# Generated deterministically by seda-macro-lef-normalizer-v1; recipe orfs-asap7-fakeram-m4-v1.
VERSION 5.8 ;
BUSBITCHARS "[]" ;
DIVIDERCHAR "/" ;

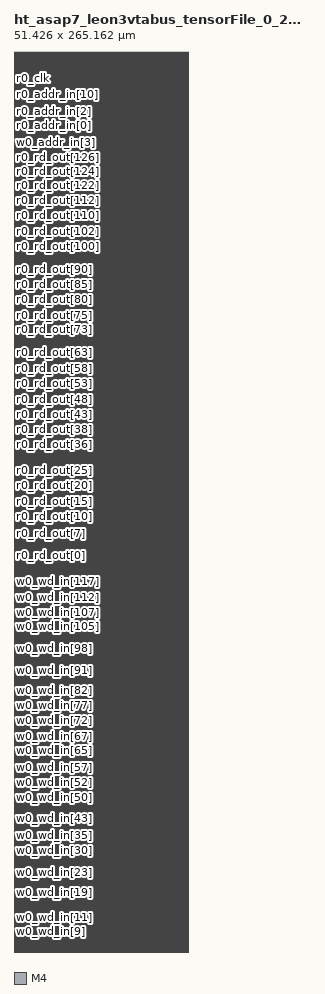
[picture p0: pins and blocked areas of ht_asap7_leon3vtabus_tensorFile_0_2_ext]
MACRO ht_asap7_leon3vtabus_tensorFile_0_2_ext
  FOREIGN ht_asap7_leon3vtabus_tensorFile_0_2_ext 0 0 ;
  CLASS BLOCK ;
  ORIGIN 0 0 ;
  SIZE 51.426 BY 265.162 ;
  SYMMETRY X Y R90 ;
  PIN w0_wd_in[0]
    DIRECTION INPUT ;
    USE SIGNAL ;
    SHAPE ABUTMENT ;
    PORT
      LAYER M4 ;
      RECT 0 0.048 0.024 0.072 ;
    END
  END w0_wd_in[0]
  PIN w0_wd_in[1]
    DIRECTION INPUT ;
    USE SIGNAL ;
    SHAPE ABUTMENT ;
    PORT
      LAYER M4 ;
      RECT 0 0.96 0.024 0.984 ;
    END
  END w0_wd_in[1]
  PIN w0_wd_in[2]
    DIRECTION INPUT ;
    USE SIGNAL ;
    SHAPE ABUTMENT ;
    PORT
      LAYER M4 ;
      RECT 0 1.872 0.024 1.896 ;
    END
  END w0_wd_in[2]
  PIN w0_wd_in[3]
    DIRECTION INPUT ;
    USE SIGNAL ;
    SHAPE ABUTMENT ;
    PORT
      LAYER M4 ;
      RECT 0 2.784 0.024 2.808 ;
    END
  END w0_wd_in[3]
  PIN w0_wd_in[4]
    DIRECTION INPUT ;
    USE SIGNAL ;
    SHAPE ABUTMENT ;
    PORT
      LAYER M4 ;
      RECT 0 3.696 0.024 3.72 ;
    END
  END w0_wd_in[4]
  PIN w0_wd_in[5]
    DIRECTION INPUT ;
    USE SIGNAL ;
    SHAPE ABUTMENT ;
    PORT
      LAYER M4 ;
      RECT 0 4.608 0.024 4.632 ;
    END
  END w0_wd_in[5]
  PIN w0_wd_in[6]
    DIRECTION INPUT ;
    USE SIGNAL ;
    SHAPE ABUTMENT ;
    PORT
      LAYER M4 ;
      RECT 0 5.52 0.024 5.544 ;
    END
  END w0_wd_in[6]
  PIN w0_wd_in[7]
    DIRECTION INPUT ;
    USE SIGNAL ;
    SHAPE ABUTMENT ;
    PORT
      LAYER M4 ;
      RECT 0 6.432 0.024 6.456 ;
    END
  END w0_wd_in[7]
  PIN w0_wd_in[8]
    DIRECTION INPUT ;
    USE SIGNAL ;
    SHAPE ABUTMENT ;
    PORT
      LAYER M4 ;
      RECT 0 7.344 0.024 7.368 ;
    END
  END w0_wd_in[8]
  PIN w0_wd_in[9]
    DIRECTION INPUT ;
    USE SIGNAL ;
    SHAPE ABUTMENT ;
    PORT
      LAYER M4 ;
      RECT 0 8.256 0.024 8.28 ;
    END
  END w0_wd_in[9]
  PIN w0_wd_in[10]
    DIRECTION INPUT ;
    USE SIGNAL ;
    SHAPE ABUTMENT ;
    PORT
      LAYER M4 ;
      RECT 0 9.168 0.024 9.192 ;
    END
  END w0_wd_in[10]
  PIN w0_wd_in[11]
    DIRECTION INPUT ;
    USE SIGNAL ;
    SHAPE ABUTMENT ;
    PORT
      LAYER M4 ;
      RECT 0 10.08 0.024 10.104 ;
    END
  END w0_wd_in[11]
  PIN w0_wd_in[12]
    DIRECTION INPUT ;
    USE SIGNAL ;
    SHAPE ABUTMENT ;
    PORT
      LAYER M4 ;
      RECT 0 10.992 0.024 11.016 ;
    END
  END w0_wd_in[12]
  PIN w0_wd_in[13]
    DIRECTION INPUT ;
    USE SIGNAL ;
    SHAPE ABUTMENT ;
    PORT
      LAYER M4 ;
      RECT 0 11.904 0.024 11.928 ;
    END
  END w0_wd_in[13]
  PIN w0_wd_in[14]
    DIRECTION INPUT ;
    USE SIGNAL ;
    SHAPE ABUTMENT ;
    PORT
      LAYER M4 ;
      RECT 0 12.816 0.024 12.84 ;
    END
  END w0_wd_in[14]
  PIN w0_wd_in[15]
    DIRECTION INPUT ;
    USE SIGNAL ;
    SHAPE ABUTMENT ;
    PORT
      LAYER M4 ;
      RECT 0 13.728 0.024 13.752 ;
    END
  END w0_wd_in[15]
  PIN w0_wd_in[16]
    DIRECTION INPUT ;
    USE SIGNAL ;
    SHAPE ABUTMENT ;
    PORT
      LAYER M4 ;
      RECT 0 14.64 0.024 14.664 ;
    END
  END w0_wd_in[16]
  PIN w0_wd_in[17]
    DIRECTION INPUT ;
    USE SIGNAL ;
    SHAPE ABUTMENT ;
    PORT
      LAYER M4 ;
      RECT 0 15.552 0.024 15.576 ;
    END
  END w0_wd_in[17]
  PIN w0_wd_in[18]
    DIRECTION INPUT ;
    USE SIGNAL ;
    SHAPE ABUTMENT ;
    PORT
      LAYER M4 ;
      RECT 0 16.464 0.024 16.488 ;
    END
  END w0_wd_in[18]
  PIN w0_wd_in[19]
    DIRECTION INPUT ;
    USE SIGNAL ;
    SHAPE ABUTMENT ;
    PORT
      LAYER M4 ;
      RECT 0 17.376 0.024 17.4 ;
    END
  END w0_wd_in[19]
  PIN w0_wd_in[20]
    DIRECTION INPUT ;
    USE SIGNAL ;
    SHAPE ABUTMENT ;
    PORT
      LAYER M4 ;
      RECT 0 18.288 0.024 18.312 ;
    END
  END w0_wd_in[20]
  PIN w0_wd_in[21]
    DIRECTION INPUT ;
    USE SIGNAL ;
    SHAPE ABUTMENT ;
    PORT
      LAYER M4 ;
      RECT 0 19.2 0.024 19.224 ;
    END
  END w0_wd_in[21]
  PIN w0_wd_in[22]
    DIRECTION INPUT ;
    USE SIGNAL ;
    SHAPE ABUTMENT ;
    PORT
      LAYER M4 ;
      RECT 0 20.112 0.024 20.136 ;
    END
  END w0_wd_in[22]
  PIN w0_wd_in[23]
    DIRECTION INPUT ;
    USE SIGNAL ;
    SHAPE ABUTMENT ;
    PORT
      LAYER M4 ;
      RECT 0 21.024 0.024 21.048 ;
    END
  END w0_wd_in[23]
  PIN w0_wd_in[24]
    DIRECTION INPUT ;
    USE SIGNAL ;
    SHAPE ABUTMENT ;
    PORT
      LAYER M4 ;
      RECT 0 21.936 0.024 21.96 ;
    END
  END w0_wd_in[24]
  PIN w0_wd_in[25]
    DIRECTION INPUT ;
    USE SIGNAL ;
    SHAPE ABUTMENT ;
    PORT
      LAYER M4 ;
      RECT 0 22.848 0.024 22.872 ;
    END
  END w0_wd_in[25]
  PIN w0_wd_in[26]
    DIRECTION INPUT ;
    USE SIGNAL ;
    SHAPE ABUTMENT ;
    PORT
      LAYER M4 ;
      RECT 0 23.76 0.024 23.784 ;
    END
  END w0_wd_in[26]
  PIN w0_wd_in[27]
    DIRECTION INPUT ;
    USE SIGNAL ;
    SHAPE ABUTMENT ;
    PORT
      LAYER M4 ;
      RECT 0 24.672 0.024 24.696 ;
    END
  END w0_wd_in[27]
  PIN w0_wd_in[28]
    DIRECTION INPUT ;
    USE SIGNAL ;
    SHAPE ABUTMENT ;
    PORT
      LAYER M4 ;
      RECT 0 25.584 0.024 25.608 ;
    END
  END w0_wd_in[28]
  PIN w0_wd_in[29]
    DIRECTION INPUT ;
    USE SIGNAL ;
    SHAPE ABUTMENT ;
    PORT
      LAYER M4 ;
      RECT 0 26.496 0.024 26.52 ;
    END
  END w0_wd_in[29]
  PIN w0_wd_in[30]
    DIRECTION INPUT ;
    USE SIGNAL ;
    SHAPE ABUTMENT ;
    PORT
      LAYER M4 ;
      RECT 0 27.408 0.024 27.432 ;
    END
  END w0_wd_in[30]
  PIN w0_wd_in[31]
    DIRECTION INPUT ;
    USE SIGNAL ;
    SHAPE ABUTMENT ;
    PORT
      LAYER M4 ;
      RECT 0 28.32 0.024 28.344 ;
    END
  END w0_wd_in[31]
  PIN w0_wd_in[32]
    DIRECTION INPUT ;
    USE SIGNAL ;
    SHAPE ABUTMENT ;
    PORT
      LAYER M4 ;
      RECT 0 29.232 0.024 29.256 ;
    END
  END w0_wd_in[32]
  PIN w0_wd_in[33]
    DIRECTION INPUT ;
    USE SIGNAL ;
    SHAPE ABUTMENT ;
    PORT
      LAYER M4 ;
      RECT 0 30.144 0.024 30.168 ;
    END
  END w0_wd_in[33]
  PIN w0_wd_in[34]
    DIRECTION INPUT ;
    USE SIGNAL ;
    SHAPE ABUTMENT ;
    PORT
      LAYER M4 ;
      RECT 0 31.056 0.024 31.08 ;
    END
  END w0_wd_in[34]
  PIN w0_wd_in[35]
    DIRECTION INPUT ;
    USE SIGNAL ;
    SHAPE ABUTMENT ;
    PORT
      LAYER M4 ;
      RECT 0 31.968 0.024 31.992 ;
    END
  END w0_wd_in[35]
  PIN w0_wd_in[36]
    DIRECTION INPUT ;
    USE SIGNAL ;
    SHAPE ABUTMENT ;
    PORT
      LAYER M4 ;
      RECT 0 32.88 0.024 32.904 ;
    END
  END w0_wd_in[36]
  PIN w0_wd_in[37]
    DIRECTION INPUT ;
    USE SIGNAL ;
    SHAPE ABUTMENT ;
    PORT
      LAYER M4 ;
      RECT 0 33.792 0.024 33.816 ;
    END
  END w0_wd_in[37]
  PIN w0_wd_in[38]
    DIRECTION INPUT ;
    USE SIGNAL ;
    SHAPE ABUTMENT ;
    PORT
      LAYER M4 ;
      RECT 0 34.704 0.024 34.728 ;
    END
  END w0_wd_in[38]
  PIN w0_wd_in[39]
    DIRECTION INPUT ;
    USE SIGNAL ;
    SHAPE ABUTMENT ;
    PORT
      LAYER M4 ;
      RECT 0 35.616 0.024 35.64 ;
    END
  END w0_wd_in[39]
  PIN w0_wd_in[40]
    DIRECTION INPUT ;
    USE SIGNAL ;
    SHAPE ABUTMENT ;
    PORT
      LAYER M4 ;
      RECT 0 36.528 0.024 36.552 ;
    END
  END w0_wd_in[40]
  PIN w0_wd_in[41]
    DIRECTION INPUT ;
    USE SIGNAL ;
    SHAPE ABUTMENT ;
    PORT
      LAYER M4 ;
      RECT 0 37.44 0.024 37.464 ;
    END
  END w0_wd_in[41]
  PIN w0_wd_in[42]
    DIRECTION INPUT ;
    USE SIGNAL ;
    SHAPE ABUTMENT ;
    PORT
      LAYER M4 ;
      RECT 0 38.352 0.024 38.376 ;
    END
  END w0_wd_in[42]
  PIN w0_wd_in[43]
    DIRECTION INPUT ;
    USE SIGNAL ;
    SHAPE ABUTMENT ;
    PORT
      LAYER M4 ;
      RECT 0 39.264 0.024 39.288 ;
    END
  END w0_wd_in[43]
  PIN w0_wd_in[44]
    DIRECTION INPUT ;
    USE SIGNAL ;
    SHAPE ABUTMENT ;
    PORT
      LAYER M4 ;
      RECT 0 40.176 0.024 40.2 ;
    END
  END w0_wd_in[44]
  PIN w0_wd_in[45]
    DIRECTION INPUT ;
    USE SIGNAL ;
    SHAPE ABUTMENT ;
    PORT
      LAYER M4 ;
      RECT 0 41.088 0.024 41.112 ;
    END
  END w0_wd_in[45]
  PIN w0_wd_in[46]
    DIRECTION INPUT ;
    USE SIGNAL ;
    SHAPE ABUTMENT ;
    PORT
      LAYER M4 ;
      RECT 0 42 0.024 42.024 ;
    END
  END w0_wd_in[46]
  PIN w0_wd_in[47]
    DIRECTION INPUT ;
    USE SIGNAL ;
    SHAPE ABUTMENT ;
    PORT
      LAYER M4 ;
      RECT 0 42.912 0.024 42.936 ;
    END
  END w0_wd_in[47]
  PIN w0_wd_in[48]
    DIRECTION INPUT ;
    USE SIGNAL ;
    SHAPE ABUTMENT ;
    PORT
      LAYER M4 ;
      RECT 0 43.824 0.024 43.848 ;
    END
  END w0_wd_in[48]
  PIN w0_wd_in[49]
    DIRECTION INPUT ;
    USE SIGNAL ;
    SHAPE ABUTMENT ;
    PORT
      LAYER M4 ;
      RECT 0 44.736 0.024 44.76 ;
    END
  END w0_wd_in[49]
  PIN w0_wd_in[50]
    DIRECTION INPUT ;
    USE SIGNAL ;
    SHAPE ABUTMENT ;
    PORT
      LAYER M4 ;
      RECT 0 45.648 0.024 45.672 ;
    END
  END w0_wd_in[50]
  PIN w0_wd_in[51]
    DIRECTION INPUT ;
    USE SIGNAL ;
    SHAPE ABUTMENT ;
    PORT
      LAYER M4 ;
      RECT 0 46.56 0.024 46.584 ;
    END
  END w0_wd_in[51]
  PIN w0_wd_in[52]
    DIRECTION INPUT ;
    USE SIGNAL ;
    SHAPE ABUTMENT ;
    PORT
      LAYER M4 ;
      RECT 0 47.472 0.024 47.496 ;
    END
  END w0_wd_in[52]
  PIN w0_wd_in[53]
    DIRECTION INPUT ;
    USE SIGNAL ;
    SHAPE ABUTMENT ;
    PORT
      LAYER M4 ;
      RECT 0 48.384 0.024 48.408 ;
    END
  END w0_wd_in[53]
  PIN w0_wd_in[54]
    DIRECTION INPUT ;
    USE SIGNAL ;
    SHAPE ABUTMENT ;
    PORT
      LAYER M4 ;
      RECT 0 49.296 0.024 49.32 ;
    END
  END w0_wd_in[54]
  PIN w0_wd_in[55]
    DIRECTION INPUT ;
    USE SIGNAL ;
    SHAPE ABUTMENT ;
    PORT
      LAYER M4 ;
      RECT 0 50.208 0.024 50.232 ;
    END
  END w0_wd_in[55]
  PIN w0_wd_in[56]
    DIRECTION INPUT ;
    USE SIGNAL ;
    SHAPE ABUTMENT ;
    PORT
      LAYER M4 ;
      RECT 0 51.12 0.024 51.144 ;
    END
  END w0_wd_in[56]
  PIN w0_wd_in[57]
    DIRECTION INPUT ;
    USE SIGNAL ;
    SHAPE ABUTMENT ;
    PORT
      LAYER M4 ;
      RECT 0 52.032 0.024 52.056 ;
    END
  END w0_wd_in[57]
  PIN w0_wd_in[58]
    DIRECTION INPUT ;
    USE SIGNAL ;
    SHAPE ABUTMENT ;
    PORT
      LAYER M4 ;
      RECT 0 52.944 0.024 52.968 ;
    END
  END w0_wd_in[58]
  PIN w0_wd_in[59]
    DIRECTION INPUT ;
    USE SIGNAL ;
    SHAPE ABUTMENT ;
    PORT
      LAYER M4 ;
      RECT 0 53.856 0.024 53.88 ;
    END
  END w0_wd_in[59]
  PIN w0_wd_in[60]
    DIRECTION INPUT ;
    USE SIGNAL ;
    SHAPE ABUTMENT ;
    PORT
      LAYER M4 ;
      RECT 0 54.768 0.024 54.792 ;
    END
  END w0_wd_in[60]
  PIN w0_wd_in[61]
    DIRECTION INPUT ;
    USE SIGNAL ;
    SHAPE ABUTMENT ;
    PORT
      LAYER M4 ;
      RECT 0 55.68 0.024 55.704 ;
    END
  END w0_wd_in[61]
  PIN w0_wd_in[62]
    DIRECTION INPUT ;
    USE SIGNAL ;
    SHAPE ABUTMENT ;
    PORT
      LAYER M4 ;
      RECT 0 56.592 0.024 56.616 ;
    END
  END w0_wd_in[62]
  PIN w0_wd_in[63]
    DIRECTION INPUT ;
    USE SIGNAL ;
    SHAPE ABUTMENT ;
    PORT
      LAYER M4 ;
      RECT 0 57.504 0.024 57.528 ;
    END
  END w0_wd_in[63]
  PIN w0_wd_in[64]
    DIRECTION INPUT ;
    USE SIGNAL ;
    SHAPE ABUTMENT ;
    PORT
      LAYER M4 ;
      RECT 0 58.416 0.024 58.44 ;
    END
  END w0_wd_in[64]
  PIN w0_wd_in[65]
    DIRECTION INPUT ;
    USE SIGNAL ;
    SHAPE ABUTMENT ;
    PORT
      LAYER M4 ;
      RECT 0 59.328 0.024 59.352 ;
    END
  END w0_wd_in[65]
  PIN w0_wd_in[66]
    DIRECTION INPUT ;
    USE SIGNAL ;
    SHAPE ABUTMENT ;
    PORT
      LAYER M4 ;
      RECT 0 60.24 0.024 60.264 ;
    END
  END w0_wd_in[66]
  PIN w0_wd_in[67]
    DIRECTION INPUT ;
    USE SIGNAL ;
    SHAPE ABUTMENT ;
    PORT
      LAYER M4 ;
      RECT 0 61.152 0.024 61.176 ;
    END
  END w0_wd_in[67]
  PIN w0_wd_in[68]
    DIRECTION INPUT ;
    USE SIGNAL ;
    SHAPE ABUTMENT ;
    PORT
      LAYER M4 ;
      RECT 0 62.064 0.024 62.088 ;
    END
  END w0_wd_in[68]
  PIN w0_wd_in[69]
    DIRECTION INPUT ;
    USE SIGNAL ;
    SHAPE ABUTMENT ;
    PORT
      LAYER M4 ;
      RECT 0 62.976 0.024 63 ;
    END
  END w0_wd_in[69]
  PIN w0_wd_in[70]
    DIRECTION INPUT ;
    USE SIGNAL ;
    SHAPE ABUTMENT ;
    PORT
      LAYER M4 ;
      RECT 0 63.888 0.024 63.912 ;
    END
  END w0_wd_in[70]
  PIN w0_wd_in[71]
    DIRECTION INPUT ;
    USE SIGNAL ;
    SHAPE ABUTMENT ;
    PORT
      LAYER M4 ;
      RECT 0 64.8 0.024 64.824 ;
    END
  END w0_wd_in[71]
  PIN w0_wd_in[72]
    DIRECTION INPUT ;
    USE SIGNAL ;
    SHAPE ABUTMENT ;
    PORT
      LAYER M4 ;
      RECT 0 65.712 0.024 65.736 ;
    END
  END w0_wd_in[72]
  PIN w0_wd_in[73]
    DIRECTION INPUT ;
    USE SIGNAL ;
    SHAPE ABUTMENT ;
    PORT
      LAYER M4 ;
      RECT 0 66.624 0.024 66.648 ;
    END
  END w0_wd_in[73]
  PIN w0_wd_in[74]
    DIRECTION INPUT ;
    USE SIGNAL ;
    SHAPE ABUTMENT ;
    PORT
      LAYER M4 ;
      RECT 0 67.536 0.024 67.56 ;
    END
  END w0_wd_in[74]
  PIN w0_wd_in[75]
    DIRECTION INPUT ;
    USE SIGNAL ;
    SHAPE ABUTMENT ;
    PORT
      LAYER M4 ;
      RECT 0 68.448 0.024 68.472 ;
    END
  END w0_wd_in[75]
  PIN w0_wd_in[76]
    DIRECTION INPUT ;
    USE SIGNAL ;
    SHAPE ABUTMENT ;
    PORT
      LAYER M4 ;
      RECT 0 69.36 0.024 69.384 ;
    END
  END w0_wd_in[76]
  PIN w0_wd_in[77]
    DIRECTION INPUT ;
    USE SIGNAL ;
    SHAPE ABUTMENT ;
    PORT
      LAYER M4 ;
      RECT 0 70.272 0.024 70.296 ;
    END
  END w0_wd_in[77]
  PIN w0_wd_in[78]
    DIRECTION INPUT ;
    USE SIGNAL ;
    SHAPE ABUTMENT ;
    PORT
      LAYER M4 ;
      RECT 0 71.184 0.024 71.208 ;
    END
  END w0_wd_in[78]
  PIN w0_wd_in[79]
    DIRECTION INPUT ;
    USE SIGNAL ;
    SHAPE ABUTMENT ;
    PORT
      LAYER M4 ;
      RECT 0 72.096 0.024 72.12 ;
    END
  END w0_wd_in[79]
  PIN w0_wd_in[80]
    DIRECTION INPUT ;
    USE SIGNAL ;
    SHAPE ABUTMENT ;
    PORT
      LAYER M4 ;
      RECT 0 73.008 0.024 73.032 ;
    END
  END w0_wd_in[80]
  PIN w0_wd_in[81]
    DIRECTION INPUT ;
    USE SIGNAL ;
    SHAPE ABUTMENT ;
    PORT
      LAYER M4 ;
      RECT 0 73.92 0.024 73.944 ;
    END
  END w0_wd_in[81]
  PIN w0_wd_in[82]
    DIRECTION INPUT ;
    USE SIGNAL ;
    SHAPE ABUTMENT ;
    PORT
      LAYER M4 ;
      RECT 0 74.832 0.024 74.856 ;
    END
  END w0_wd_in[82]
  PIN w0_wd_in[83]
    DIRECTION INPUT ;
    USE SIGNAL ;
    SHAPE ABUTMENT ;
    PORT
      LAYER M4 ;
      RECT 0 75.744 0.024 75.768 ;
    END
  END w0_wd_in[83]
  PIN w0_wd_in[84]
    DIRECTION INPUT ;
    USE SIGNAL ;
    SHAPE ABUTMENT ;
    PORT
      LAYER M4 ;
      RECT 0 76.656 0.024 76.68 ;
    END
  END w0_wd_in[84]
  PIN w0_wd_in[85]
    DIRECTION INPUT ;
    USE SIGNAL ;
    SHAPE ABUTMENT ;
    PORT
      LAYER M4 ;
      RECT 0 77.568 0.024 77.592 ;
    END
  END w0_wd_in[85]
  PIN w0_wd_in[86]
    DIRECTION INPUT ;
    USE SIGNAL ;
    SHAPE ABUTMENT ;
    PORT
      LAYER M4 ;
      RECT 0 78.48 0.024 78.504 ;
    END
  END w0_wd_in[86]
  PIN w0_wd_in[87]
    DIRECTION INPUT ;
    USE SIGNAL ;
    SHAPE ABUTMENT ;
    PORT
      LAYER M4 ;
      RECT 0 79.392 0.024 79.416 ;
    END
  END w0_wd_in[87]
  PIN w0_wd_in[88]
    DIRECTION INPUT ;
    USE SIGNAL ;
    SHAPE ABUTMENT ;
    PORT
      LAYER M4 ;
      RECT 0 80.304 0.024 80.328 ;
    END
  END w0_wd_in[88]
  PIN w0_wd_in[89]
    DIRECTION INPUT ;
    USE SIGNAL ;
    SHAPE ABUTMENT ;
    PORT
      LAYER M4 ;
      RECT 0 81.216 0.024 81.24 ;
    END
  END w0_wd_in[89]
  PIN w0_wd_in[90]
    DIRECTION INPUT ;
    USE SIGNAL ;
    SHAPE ABUTMENT ;
    PORT
      LAYER M4 ;
      RECT 0 82.128 0.024 82.152 ;
    END
  END w0_wd_in[90]
  PIN w0_wd_in[91]
    DIRECTION INPUT ;
    USE SIGNAL ;
    SHAPE ABUTMENT ;
    PORT
      LAYER M4 ;
      RECT 0 83.04 0.024 83.064 ;
    END
  END w0_wd_in[91]
  PIN w0_wd_in[92]
    DIRECTION INPUT ;
    USE SIGNAL ;
    SHAPE ABUTMENT ;
    PORT
      LAYER M4 ;
      RECT 0 83.952 0.024 83.976 ;
    END
  END w0_wd_in[92]
  PIN w0_wd_in[93]
    DIRECTION INPUT ;
    USE SIGNAL ;
    SHAPE ABUTMENT ;
    PORT
      LAYER M4 ;
      RECT 0 84.864 0.024 84.888 ;
    END
  END w0_wd_in[93]
  PIN w0_wd_in[94]
    DIRECTION INPUT ;
    USE SIGNAL ;
    SHAPE ABUTMENT ;
    PORT
      LAYER M4 ;
      RECT 0 85.776 0.024 85.8 ;
    END
  END w0_wd_in[94]
  PIN w0_wd_in[95]
    DIRECTION INPUT ;
    USE SIGNAL ;
    SHAPE ABUTMENT ;
    PORT
      LAYER M4 ;
      RECT 0 86.688 0.024 86.712 ;
    END
  END w0_wd_in[95]
  PIN w0_wd_in[96]
    DIRECTION INPUT ;
    USE SIGNAL ;
    SHAPE ABUTMENT ;
    PORT
      LAYER M4 ;
      RECT 0 87.6 0.024 87.624 ;
    END
  END w0_wd_in[96]
  PIN w0_wd_in[97]
    DIRECTION INPUT ;
    USE SIGNAL ;
    SHAPE ABUTMENT ;
    PORT
      LAYER M4 ;
      RECT 0 88.512 0.024 88.536 ;
    END
  END w0_wd_in[97]
  PIN w0_wd_in[98]
    DIRECTION INPUT ;
    USE SIGNAL ;
    SHAPE ABUTMENT ;
    PORT
      LAYER M4 ;
      RECT 0 89.424 0.024 89.448 ;
    END
  END w0_wd_in[98]
  PIN w0_wd_in[99]
    DIRECTION INPUT ;
    USE SIGNAL ;
    SHAPE ABUTMENT ;
    PORT
      LAYER M4 ;
      RECT 0 90.336 0.024 90.36 ;
    END
  END w0_wd_in[99]
  PIN w0_wd_in[100]
    DIRECTION INPUT ;
    USE SIGNAL ;
    SHAPE ABUTMENT ;
    PORT
      LAYER M4 ;
      RECT 0 91.248 0.024 91.272 ;
    END
  END w0_wd_in[100]
  PIN w0_wd_in[101]
    DIRECTION INPUT ;
    USE SIGNAL ;
    SHAPE ABUTMENT ;
    PORT
      LAYER M4 ;
      RECT 0 92.16 0.024 92.184 ;
    END
  END w0_wd_in[101]
  PIN w0_wd_in[102]
    DIRECTION INPUT ;
    USE SIGNAL ;
    SHAPE ABUTMENT ;
    PORT
      LAYER M4 ;
      RECT 0 93.072 0.024 93.096 ;
    END
  END w0_wd_in[102]
  PIN w0_wd_in[103]
    DIRECTION INPUT ;
    USE SIGNAL ;
    SHAPE ABUTMENT ;
    PORT
      LAYER M4 ;
      RECT 0 93.984 0.024 94.008 ;
    END
  END w0_wd_in[103]
  PIN w0_wd_in[104]
    DIRECTION INPUT ;
    USE SIGNAL ;
    SHAPE ABUTMENT ;
    PORT
      LAYER M4 ;
      RECT 0 94.896 0.024 94.92 ;
    END
  END w0_wd_in[104]
  PIN w0_wd_in[105]
    DIRECTION INPUT ;
    USE SIGNAL ;
    SHAPE ABUTMENT ;
    PORT
      LAYER M4 ;
      RECT 0 95.808 0.024 95.832 ;
    END
  END w0_wd_in[105]
  PIN w0_wd_in[106]
    DIRECTION INPUT ;
    USE SIGNAL ;
    SHAPE ABUTMENT ;
    PORT
      LAYER M4 ;
      RECT 0 96.72 0.024 96.744 ;
    END
  END w0_wd_in[106]
  PIN w0_wd_in[107]
    DIRECTION INPUT ;
    USE SIGNAL ;
    SHAPE ABUTMENT ;
    PORT
      LAYER M4 ;
      RECT 0 97.632 0.024 97.656 ;
    END
  END w0_wd_in[107]
  PIN w0_wd_in[108]
    DIRECTION INPUT ;
    USE SIGNAL ;
    SHAPE ABUTMENT ;
    PORT
      LAYER M4 ;
      RECT 0 98.544 0.024 98.568 ;
    END
  END w0_wd_in[108]
  PIN w0_wd_in[109]
    DIRECTION INPUT ;
    USE SIGNAL ;
    SHAPE ABUTMENT ;
    PORT
      LAYER M4 ;
      RECT 0 99.456 0.024 99.48 ;
    END
  END w0_wd_in[109]
  PIN w0_wd_in[110]
    DIRECTION INPUT ;
    USE SIGNAL ;
    SHAPE ABUTMENT ;
    PORT
      LAYER M4 ;
      RECT 0 100.368 0.024 100.392 ;
    END
  END w0_wd_in[110]
  PIN w0_wd_in[111]
    DIRECTION INPUT ;
    USE SIGNAL ;
    SHAPE ABUTMENT ;
    PORT
      LAYER M4 ;
      RECT 0 101.28 0.024 101.304 ;
    END
  END w0_wd_in[111]
  PIN w0_wd_in[112]
    DIRECTION INPUT ;
    USE SIGNAL ;
    SHAPE ABUTMENT ;
    PORT
      LAYER M4 ;
      RECT 0 102.192 0.024 102.216 ;
    END
  END w0_wd_in[112]
  PIN w0_wd_in[113]
    DIRECTION INPUT ;
    USE SIGNAL ;
    SHAPE ABUTMENT ;
    PORT
      LAYER M4 ;
      RECT 0 103.104 0.024 103.128 ;
    END
  END w0_wd_in[113]
  PIN w0_wd_in[114]
    DIRECTION INPUT ;
    USE SIGNAL ;
    SHAPE ABUTMENT ;
    PORT
      LAYER M4 ;
      RECT 0 104.016 0.024 104.04 ;
    END
  END w0_wd_in[114]
  PIN w0_wd_in[115]
    DIRECTION INPUT ;
    USE SIGNAL ;
    SHAPE ABUTMENT ;
    PORT
      LAYER M4 ;
      RECT 0 104.928 0.024 104.952 ;
    END
  END w0_wd_in[115]
  PIN w0_wd_in[116]
    DIRECTION INPUT ;
    USE SIGNAL ;
    SHAPE ABUTMENT ;
    PORT
      LAYER M4 ;
      RECT 0 105.84 0.024 105.864 ;
    END
  END w0_wd_in[116]
  PIN w0_wd_in[117]
    DIRECTION INPUT ;
    USE SIGNAL ;
    SHAPE ABUTMENT ;
    PORT
      LAYER M4 ;
      RECT 0 106.752 0.024 106.776 ;
    END
  END w0_wd_in[117]
  PIN w0_wd_in[118]
    DIRECTION INPUT ;
    USE SIGNAL ;
    SHAPE ABUTMENT ;
    PORT
      LAYER M4 ;
      RECT 0 107.664 0.024 107.688 ;
    END
  END w0_wd_in[118]
  PIN w0_wd_in[119]
    DIRECTION INPUT ;
    USE SIGNAL ;
    SHAPE ABUTMENT ;
    PORT
      LAYER M4 ;
      RECT 0 108.576 0.024 108.6 ;
    END
  END w0_wd_in[119]
  PIN w0_wd_in[120]
    DIRECTION INPUT ;
    USE SIGNAL ;
    SHAPE ABUTMENT ;
    PORT
      LAYER M4 ;
      RECT 0 109.488 0.024 109.512 ;
    END
  END w0_wd_in[120]
  PIN w0_wd_in[121]
    DIRECTION INPUT ;
    USE SIGNAL ;
    SHAPE ABUTMENT ;
    PORT
      LAYER M4 ;
      RECT 0 110.4 0.024 110.424 ;
    END
  END w0_wd_in[121]
  PIN w0_wd_in[122]
    DIRECTION INPUT ;
    USE SIGNAL ;
    SHAPE ABUTMENT ;
    PORT
      LAYER M4 ;
      RECT 0 111.312 0.024 111.336 ;
    END
  END w0_wd_in[122]
  PIN w0_wd_in[123]
    DIRECTION INPUT ;
    USE SIGNAL ;
    SHAPE ABUTMENT ;
    PORT
      LAYER M4 ;
      RECT 0 112.224 0.024 112.248 ;
    END
  END w0_wd_in[123]
  PIN w0_wd_in[124]
    DIRECTION INPUT ;
    USE SIGNAL ;
    SHAPE ABUTMENT ;
    PORT
      LAYER M4 ;
      RECT 0 113.136 0.024 113.16 ;
    END
  END w0_wd_in[124]
  PIN w0_wd_in[125]
    DIRECTION INPUT ;
    USE SIGNAL ;
    SHAPE ABUTMENT ;
    PORT
      LAYER M4 ;
      RECT 0 114.048 0.024 114.072 ;
    END
  END w0_wd_in[125]
  PIN w0_wd_in[126]
    DIRECTION INPUT ;
    USE SIGNAL ;
    SHAPE ABUTMENT ;
    PORT
      LAYER M4 ;
      RECT 0 114.96 0.024 114.984 ;
    END
  END w0_wd_in[126]
  PIN w0_wd_in[127]
    DIRECTION INPUT ;
    USE SIGNAL ;
    SHAPE ABUTMENT ;
    PORT
      LAYER M4 ;
      RECT 0 115.872 0.024 115.896 ;
    END
  END w0_wd_in[127]
  PIN r0_rd_out[0]
    DIRECTION OUTPUT ;
    USE SIGNAL ;
    SHAPE ABUTMENT ;
    PORT
      LAYER M4 ;
      RECT 0 116.784 0.024 116.808 ;
    END
  END r0_rd_out[0]
  PIN r0_rd_out[1]
    DIRECTION OUTPUT ;
    USE SIGNAL ;
    SHAPE ABUTMENT ;
    PORT
      LAYER M4 ;
      RECT 0 117.696 0.024 117.72 ;
    END
  END r0_rd_out[1]
  PIN r0_rd_out[2]
    DIRECTION OUTPUT ;
    USE SIGNAL ;
    SHAPE ABUTMENT ;
    PORT
      LAYER M4 ;
      RECT 0 118.608 0.024 118.632 ;
    END
  END r0_rd_out[2]
  PIN r0_rd_out[3]
    DIRECTION OUTPUT ;
    USE SIGNAL ;
    SHAPE ABUTMENT ;
    PORT
      LAYER M4 ;
      RECT 0 119.52 0.024 119.544 ;
    END
  END r0_rd_out[3]
  PIN r0_rd_out[4]
    DIRECTION OUTPUT ;
    USE SIGNAL ;
    SHAPE ABUTMENT ;
    PORT
      LAYER M4 ;
      RECT 0 120.432 0.024 120.456 ;
    END
  END r0_rd_out[4]
  PIN r0_rd_out[5]
    DIRECTION OUTPUT ;
    USE SIGNAL ;
    SHAPE ABUTMENT ;
    PORT
      LAYER M4 ;
      RECT 0 121.344 0.024 121.368 ;
    END
  END r0_rd_out[5]
  PIN r0_rd_out[6]
    DIRECTION OUTPUT ;
    USE SIGNAL ;
    SHAPE ABUTMENT ;
    PORT
      LAYER M4 ;
      RECT 0 122.256 0.024 122.28 ;
    END
  END r0_rd_out[6]
  PIN r0_rd_out[7]
    DIRECTION OUTPUT ;
    USE SIGNAL ;
    SHAPE ABUTMENT ;
    PORT
      LAYER M4 ;
      RECT 0 123.168 0.024 123.192 ;
    END
  END r0_rd_out[7]
  PIN r0_rd_out[8]
    DIRECTION OUTPUT ;
    USE SIGNAL ;
    SHAPE ABUTMENT ;
    PORT
      LAYER M4 ;
      RECT 0 124.08 0.024 124.104 ;
    END
  END r0_rd_out[8]
  PIN r0_rd_out[9]
    DIRECTION OUTPUT ;
    USE SIGNAL ;
    SHAPE ABUTMENT ;
    PORT
      LAYER M4 ;
      RECT 0 124.992 0.024 125.016 ;
    END
  END r0_rd_out[9]
  PIN r0_rd_out[10]
    DIRECTION OUTPUT ;
    USE SIGNAL ;
    SHAPE ABUTMENT ;
    PORT
      LAYER M4 ;
      RECT 0 125.904 0.024 125.928 ;
    END
  END r0_rd_out[10]
  PIN r0_rd_out[11]
    DIRECTION OUTPUT ;
    USE SIGNAL ;
    SHAPE ABUTMENT ;
    PORT
      LAYER M4 ;
      RECT 0 126.816 0.024 126.84 ;
    END
  END r0_rd_out[11]
  PIN r0_rd_out[12]
    DIRECTION OUTPUT ;
    USE SIGNAL ;
    SHAPE ABUTMENT ;
    PORT
      LAYER M4 ;
      RECT 0 127.728 0.024 127.752 ;
    END
  END r0_rd_out[12]
  PIN r0_rd_out[13]
    DIRECTION OUTPUT ;
    USE SIGNAL ;
    SHAPE ABUTMENT ;
    PORT
      LAYER M4 ;
      RECT 0 128.64 0.024 128.664 ;
    END
  END r0_rd_out[13]
  PIN r0_rd_out[14]
    DIRECTION OUTPUT ;
    USE SIGNAL ;
    SHAPE ABUTMENT ;
    PORT
      LAYER M4 ;
      RECT 0 129.552 0.024 129.576 ;
    END
  END r0_rd_out[14]
  PIN r0_rd_out[15]
    DIRECTION OUTPUT ;
    USE SIGNAL ;
    SHAPE ABUTMENT ;
    PORT
      LAYER M4 ;
      RECT 0 130.464 0.024 130.488 ;
    END
  END r0_rd_out[15]
  PIN r0_rd_out[16]
    DIRECTION OUTPUT ;
    USE SIGNAL ;
    SHAPE ABUTMENT ;
    PORT
      LAYER M4 ;
      RECT 0 131.376 0.024 131.4 ;
    END
  END r0_rd_out[16]
  PIN r0_rd_out[17]
    DIRECTION OUTPUT ;
    USE SIGNAL ;
    SHAPE ABUTMENT ;
    PORT
      LAYER M4 ;
      RECT 0 132.288 0.024 132.312 ;
    END
  END r0_rd_out[17]
  PIN r0_rd_out[18]
    DIRECTION OUTPUT ;
    USE SIGNAL ;
    SHAPE ABUTMENT ;
    PORT
      LAYER M4 ;
      RECT 0 133.2 0.024 133.224 ;
    END
  END r0_rd_out[18]
  PIN r0_rd_out[19]
    DIRECTION OUTPUT ;
    USE SIGNAL ;
    SHAPE ABUTMENT ;
    PORT
      LAYER M4 ;
      RECT 0 134.112 0.024 134.136 ;
    END
  END r0_rd_out[19]
  PIN r0_rd_out[20]
    DIRECTION OUTPUT ;
    USE SIGNAL ;
    SHAPE ABUTMENT ;
    PORT
      LAYER M4 ;
      RECT 0 135.024 0.024 135.048 ;
    END
  END r0_rd_out[20]
  PIN r0_rd_out[21]
    DIRECTION OUTPUT ;
    USE SIGNAL ;
    SHAPE ABUTMENT ;
    PORT
      LAYER M4 ;
      RECT 0 135.936 0.024 135.96 ;
    END
  END r0_rd_out[21]
  PIN r0_rd_out[22]
    DIRECTION OUTPUT ;
    USE SIGNAL ;
    SHAPE ABUTMENT ;
    PORT
      LAYER M4 ;
      RECT 0 136.848 0.024 136.872 ;
    END
  END r0_rd_out[22]
  PIN r0_rd_out[23]
    DIRECTION OUTPUT ;
    USE SIGNAL ;
    SHAPE ABUTMENT ;
    PORT
      LAYER M4 ;
      RECT 0 137.76 0.024 137.784 ;
    END
  END r0_rd_out[23]
  PIN r0_rd_out[24]
    DIRECTION OUTPUT ;
    USE SIGNAL ;
    SHAPE ABUTMENT ;
    PORT
      LAYER M4 ;
      RECT 0 138.672 0.024 138.696 ;
    END
  END r0_rd_out[24]
  PIN r0_rd_out[25]
    DIRECTION OUTPUT ;
    USE SIGNAL ;
    SHAPE ABUTMENT ;
    PORT
      LAYER M4 ;
      RECT 0 139.584 0.024 139.608 ;
    END
  END r0_rd_out[25]
  PIN r0_rd_out[26]
    DIRECTION OUTPUT ;
    USE SIGNAL ;
    SHAPE ABUTMENT ;
    PORT
      LAYER M4 ;
      RECT 0 140.496 0.024 140.52 ;
    END
  END r0_rd_out[26]
  PIN r0_rd_out[27]
    DIRECTION OUTPUT ;
    USE SIGNAL ;
    SHAPE ABUTMENT ;
    PORT
      LAYER M4 ;
      RECT 0 141.408 0.024 141.432 ;
    END
  END r0_rd_out[27]
  PIN r0_rd_out[28]
    DIRECTION OUTPUT ;
    USE SIGNAL ;
    SHAPE ABUTMENT ;
    PORT
      LAYER M4 ;
      RECT 0 142.32 0.024 142.344 ;
    END
  END r0_rd_out[28]
  PIN r0_rd_out[29]
    DIRECTION OUTPUT ;
    USE SIGNAL ;
    SHAPE ABUTMENT ;
    PORT
      LAYER M4 ;
      RECT 0 143.232 0.024 143.256 ;
    END
  END r0_rd_out[29]
  PIN r0_rd_out[30]
    DIRECTION OUTPUT ;
    USE SIGNAL ;
    SHAPE ABUTMENT ;
    PORT
      LAYER M4 ;
      RECT 0 144.144 0.024 144.168 ;
    END
  END r0_rd_out[30]
  PIN r0_rd_out[31]
    DIRECTION OUTPUT ;
    USE SIGNAL ;
    SHAPE ABUTMENT ;
    PORT
      LAYER M4 ;
      RECT 0 145.056 0.024 145.08 ;
    END
  END r0_rd_out[31]
  PIN r0_rd_out[32]
    DIRECTION OUTPUT ;
    USE SIGNAL ;
    SHAPE ABUTMENT ;
    PORT
      LAYER M4 ;
      RECT 0 145.968 0.024 145.992 ;
    END
  END r0_rd_out[32]
  PIN r0_rd_out[33]
    DIRECTION OUTPUT ;
    USE SIGNAL ;
    SHAPE ABUTMENT ;
    PORT
      LAYER M4 ;
      RECT 0 146.88 0.024 146.904 ;
    END
  END r0_rd_out[33]
  PIN r0_rd_out[34]
    DIRECTION OUTPUT ;
    USE SIGNAL ;
    SHAPE ABUTMENT ;
    PORT
      LAYER M4 ;
      RECT 0 147.792 0.024 147.816 ;
    END
  END r0_rd_out[34]
  PIN r0_rd_out[35]
    DIRECTION OUTPUT ;
    USE SIGNAL ;
    SHAPE ABUTMENT ;
    PORT
      LAYER M4 ;
      RECT 0 148.704 0.024 148.728 ;
    END
  END r0_rd_out[35]
  PIN r0_rd_out[36]
    DIRECTION OUTPUT ;
    USE SIGNAL ;
    SHAPE ABUTMENT ;
    PORT
      LAYER M4 ;
      RECT 0 149.616 0.024 149.64 ;
    END
  END r0_rd_out[36]
  PIN r0_rd_out[37]
    DIRECTION OUTPUT ;
    USE SIGNAL ;
    SHAPE ABUTMENT ;
    PORT
      LAYER M4 ;
      RECT 0 150.528 0.024 150.552 ;
    END
  END r0_rd_out[37]
  PIN r0_rd_out[38]
    DIRECTION OUTPUT ;
    USE SIGNAL ;
    SHAPE ABUTMENT ;
    PORT
      LAYER M4 ;
      RECT 0 151.44 0.024 151.464 ;
    END
  END r0_rd_out[38]
  PIN r0_rd_out[39]
    DIRECTION OUTPUT ;
    USE SIGNAL ;
    SHAPE ABUTMENT ;
    PORT
      LAYER M4 ;
      RECT 0 152.352 0.024 152.376 ;
    END
  END r0_rd_out[39]
  PIN r0_rd_out[40]
    DIRECTION OUTPUT ;
    USE SIGNAL ;
    SHAPE ABUTMENT ;
    PORT
      LAYER M4 ;
      RECT 0 153.264 0.024 153.288 ;
    END
  END r0_rd_out[40]
  PIN r0_rd_out[41]
    DIRECTION OUTPUT ;
    USE SIGNAL ;
    SHAPE ABUTMENT ;
    PORT
      LAYER M4 ;
      RECT 0 154.176 0.024 154.2 ;
    END
  END r0_rd_out[41]
  PIN r0_rd_out[42]
    DIRECTION OUTPUT ;
    USE SIGNAL ;
    SHAPE ABUTMENT ;
    PORT
      LAYER M4 ;
      RECT 0 155.088 0.024 155.112 ;
    END
  END r0_rd_out[42]
  PIN r0_rd_out[43]
    DIRECTION OUTPUT ;
    USE SIGNAL ;
    SHAPE ABUTMENT ;
    PORT
      LAYER M4 ;
      RECT 0 156 0.024 156.024 ;
    END
  END r0_rd_out[43]
  PIN r0_rd_out[44]
    DIRECTION OUTPUT ;
    USE SIGNAL ;
    SHAPE ABUTMENT ;
    PORT
      LAYER M4 ;
      RECT 0 156.912 0.024 156.936 ;
    END
  END r0_rd_out[44]
  PIN r0_rd_out[45]
    DIRECTION OUTPUT ;
    USE SIGNAL ;
    SHAPE ABUTMENT ;
    PORT
      LAYER M4 ;
      RECT 0 157.824 0.024 157.848 ;
    END
  END r0_rd_out[45]
  PIN r0_rd_out[46]
    DIRECTION OUTPUT ;
    USE SIGNAL ;
    SHAPE ABUTMENT ;
    PORT
      LAYER M4 ;
      RECT 0 158.736 0.024 158.76 ;
    END
  END r0_rd_out[46]
  PIN r0_rd_out[47]
    DIRECTION OUTPUT ;
    USE SIGNAL ;
    SHAPE ABUTMENT ;
    PORT
      LAYER M4 ;
      RECT 0 159.648 0.024 159.672 ;
    END
  END r0_rd_out[47]
  PIN r0_rd_out[48]
    DIRECTION OUTPUT ;
    USE SIGNAL ;
    SHAPE ABUTMENT ;
    PORT
      LAYER M4 ;
      RECT 0 160.56 0.024 160.584 ;
    END
  END r0_rd_out[48]
  PIN r0_rd_out[49]
    DIRECTION OUTPUT ;
    USE SIGNAL ;
    SHAPE ABUTMENT ;
    PORT
      LAYER M4 ;
      RECT 0 161.472 0.024 161.496 ;
    END
  END r0_rd_out[49]
  PIN r0_rd_out[50]
    DIRECTION OUTPUT ;
    USE SIGNAL ;
    SHAPE ABUTMENT ;
    PORT
      LAYER M4 ;
      RECT 0 162.384 0.024 162.408 ;
    END
  END r0_rd_out[50]
  PIN r0_rd_out[51]
    DIRECTION OUTPUT ;
    USE SIGNAL ;
    SHAPE ABUTMENT ;
    PORT
      LAYER M4 ;
      RECT 0 163.296 0.024 163.32 ;
    END
  END r0_rd_out[51]
  PIN r0_rd_out[52]
    DIRECTION OUTPUT ;
    USE SIGNAL ;
    SHAPE ABUTMENT ;
    PORT
      LAYER M4 ;
      RECT 0 164.208 0.024 164.232 ;
    END
  END r0_rd_out[52]
  PIN r0_rd_out[53]
    DIRECTION OUTPUT ;
    USE SIGNAL ;
    SHAPE ABUTMENT ;
    PORT
      LAYER M4 ;
      RECT 0 165.12 0.024 165.144 ;
    END
  END r0_rd_out[53]
  PIN r0_rd_out[54]
    DIRECTION OUTPUT ;
    USE SIGNAL ;
    SHAPE ABUTMENT ;
    PORT
      LAYER M4 ;
      RECT 0 166.032 0.024 166.056 ;
    END
  END r0_rd_out[54]
  PIN r0_rd_out[55]
    DIRECTION OUTPUT ;
    USE SIGNAL ;
    SHAPE ABUTMENT ;
    PORT
      LAYER M4 ;
      RECT 0 166.944 0.024 166.968 ;
    END
  END r0_rd_out[55]
  PIN r0_rd_out[56]
    DIRECTION OUTPUT ;
    USE SIGNAL ;
    SHAPE ABUTMENT ;
    PORT
      LAYER M4 ;
      RECT 0 167.856 0.024 167.88 ;
    END
  END r0_rd_out[56]
  PIN r0_rd_out[57]
    DIRECTION OUTPUT ;
    USE SIGNAL ;
    SHAPE ABUTMENT ;
    PORT
      LAYER M4 ;
      RECT 0 168.768 0.024 168.792 ;
    END
  END r0_rd_out[57]
  PIN r0_rd_out[58]
    DIRECTION OUTPUT ;
    USE SIGNAL ;
    SHAPE ABUTMENT ;
    PORT
      LAYER M4 ;
      RECT 0 169.68 0.024 169.704 ;
    END
  END r0_rd_out[58]
  PIN r0_rd_out[59]
    DIRECTION OUTPUT ;
    USE SIGNAL ;
    SHAPE ABUTMENT ;
    PORT
      LAYER M4 ;
      RECT 0 170.592 0.024 170.616 ;
    END
  END r0_rd_out[59]
  PIN r0_rd_out[60]
    DIRECTION OUTPUT ;
    USE SIGNAL ;
    SHAPE ABUTMENT ;
    PORT
      LAYER M4 ;
      RECT 0 171.504 0.024 171.528 ;
    END
  END r0_rd_out[60]
  PIN r0_rd_out[61]
    DIRECTION OUTPUT ;
    USE SIGNAL ;
    SHAPE ABUTMENT ;
    PORT
      LAYER M4 ;
      RECT 0 172.416 0.024 172.44 ;
    END
  END r0_rd_out[61]
  PIN r0_rd_out[62]
    DIRECTION OUTPUT ;
    USE SIGNAL ;
    SHAPE ABUTMENT ;
    PORT
      LAYER M4 ;
      RECT 0 173.328 0.024 173.352 ;
    END
  END r0_rd_out[62]
  PIN r0_rd_out[63]
    DIRECTION OUTPUT ;
    USE SIGNAL ;
    SHAPE ABUTMENT ;
    PORT
      LAYER M4 ;
      RECT 0 174.24 0.024 174.264 ;
    END
  END r0_rd_out[63]
  PIN r0_rd_out[64]
    DIRECTION OUTPUT ;
    USE SIGNAL ;
    SHAPE ABUTMENT ;
    PORT
      LAYER M4 ;
      RECT 0 175.152 0.024 175.176 ;
    END
  END r0_rd_out[64]
  PIN r0_rd_out[65]
    DIRECTION OUTPUT ;
    USE SIGNAL ;
    SHAPE ABUTMENT ;
    PORT
      LAYER M4 ;
      RECT 0 176.064 0.024 176.088 ;
    END
  END r0_rd_out[65]
  PIN r0_rd_out[66]
    DIRECTION OUTPUT ;
    USE SIGNAL ;
    SHAPE ABUTMENT ;
    PORT
      LAYER M4 ;
      RECT 0 176.976 0.024 177 ;
    END
  END r0_rd_out[66]
  PIN r0_rd_out[67]
    DIRECTION OUTPUT ;
    USE SIGNAL ;
    SHAPE ABUTMENT ;
    PORT
      LAYER M4 ;
      RECT 0 177.888 0.024 177.912 ;
    END
  END r0_rd_out[67]
  PIN r0_rd_out[68]
    DIRECTION OUTPUT ;
    USE SIGNAL ;
    SHAPE ABUTMENT ;
    PORT
      LAYER M4 ;
      RECT 0 178.8 0.024 178.824 ;
    END
  END r0_rd_out[68]
  PIN r0_rd_out[69]
    DIRECTION OUTPUT ;
    USE SIGNAL ;
    SHAPE ABUTMENT ;
    PORT
      LAYER M4 ;
      RECT 0 179.712 0.024 179.736 ;
    END
  END r0_rd_out[69]
  PIN r0_rd_out[70]
    DIRECTION OUTPUT ;
    USE SIGNAL ;
    SHAPE ABUTMENT ;
    PORT
      LAYER M4 ;
      RECT 0 180.624 0.024 180.648 ;
    END
  END r0_rd_out[70]
  PIN r0_rd_out[71]
    DIRECTION OUTPUT ;
    USE SIGNAL ;
    SHAPE ABUTMENT ;
    PORT
      LAYER M4 ;
      RECT 0 181.536 0.024 181.56 ;
    END
  END r0_rd_out[71]
  PIN r0_rd_out[72]
    DIRECTION OUTPUT ;
    USE SIGNAL ;
    SHAPE ABUTMENT ;
    PORT
      LAYER M4 ;
      RECT 0 182.448 0.024 182.472 ;
    END
  END r0_rd_out[72]
  PIN r0_rd_out[73]
    DIRECTION OUTPUT ;
    USE SIGNAL ;
    SHAPE ABUTMENT ;
    PORT
      LAYER M4 ;
      RECT 0 183.36 0.024 183.384 ;
    END
  END r0_rd_out[73]
  PIN r0_rd_out[74]
    DIRECTION OUTPUT ;
    USE SIGNAL ;
    SHAPE ABUTMENT ;
    PORT
      LAYER M4 ;
      RECT 0 184.272 0.024 184.296 ;
    END
  END r0_rd_out[74]
  PIN r0_rd_out[75]
    DIRECTION OUTPUT ;
    USE SIGNAL ;
    SHAPE ABUTMENT ;
    PORT
      LAYER M4 ;
      RECT 0 185.184 0.024 185.208 ;
    END
  END r0_rd_out[75]
  PIN r0_rd_out[76]
    DIRECTION OUTPUT ;
    USE SIGNAL ;
    SHAPE ABUTMENT ;
    PORT
      LAYER M4 ;
      RECT 0 186.096 0.024 186.12 ;
    END
  END r0_rd_out[76]
  PIN r0_rd_out[77]
    DIRECTION OUTPUT ;
    USE SIGNAL ;
    SHAPE ABUTMENT ;
    PORT
      LAYER M4 ;
      RECT 0 187.008 0.024 187.032 ;
    END
  END r0_rd_out[77]
  PIN r0_rd_out[78]
    DIRECTION OUTPUT ;
    USE SIGNAL ;
    SHAPE ABUTMENT ;
    PORT
      LAYER M4 ;
      RECT 0 187.92 0.024 187.944 ;
    END
  END r0_rd_out[78]
  PIN r0_rd_out[79]
    DIRECTION OUTPUT ;
    USE SIGNAL ;
    SHAPE ABUTMENT ;
    PORT
      LAYER M4 ;
      RECT 0 188.832 0.024 188.856 ;
    END
  END r0_rd_out[79]
  PIN r0_rd_out[80]
    DIRECTION OUTPUT ;
    USE SIGNAL ;
    SHAPE ABUTMENT ;
    PORT
      LAYER M4 ;
      RECT 0 189.744 0.024 189.768 ;
    END
  END r0_rd_out[80]
  PIN r0_rd_out[81]
    DIRECTION OUTPUT ;
    USE SIGNAL ;
    SHAPE ABUTMENT ;
    PORT
      LAYER M4 ;
      RECT 0 190.656 0.024 190.68 ;
    END
  END r0_rd_out[81]
  PIN r0_rd_out[82]
    DIRECTION OUTPUT ;
    USE SIGNAL ;
    SHAPE ABUTMENT ;
    PORT
      LAYER M4 ;
      RECT 0 191.568 0.024 191.592 ;
    END
  END r0_rd_out[82]
  PIN r0_rd_out[83]
    DIRECTION OUTPUT ;
    USE SIGNAL ;
    SHAPE ABUTMENT ;
    PORT
      LAYER M4 ;
      RECT 0 192.48 0.024 192.504 ;
    END
  END r0_rd_out[83]
  PIN r0_rd_out[84]
    DIRECTION OUTPUT ;
    USE SIGNAL ;
    SHAPE ABUTMENT ;
    PORT
      LAYER M4 ;
      RECT 0 193.392 0.024 193.416 ;
    END
  END r0_rd_out[84]
  PIN r0_rd_out[85]
    DIRECTION OUTPUT ;
    USE SIGNAL ;
    SHAPE ABUTMENT ;
    PORT
      LAYER M4 ;
      RECT 0 194.304 0.024 194.328 ;
    END
  END r0_rd_out[85]
  PIN r0_rd_out[86]
    DIRECTION OUTPUT ;
    USE SIGNAL ;
    SHAPE ABUTMENT ;
    PORT
      LAYER M4 ;
      RECT 0 195.216 0.024 195.24 ;
    END
  END r0_rd_out[86]
  PIN r0_rd_out[87]
    DIRECTION OUTPUT ;
    USE SIGNAL ;
    SHAPE ABUTMENT ;
    PORT
      LAYER M4 ;
      RECT 0 196.128 0.024 196.152 ;
    END
  END r0_rd_out[87]
  PIN r0_rd_out[88]
    DIRECTION OUTPUT ;
    USE SIGNAL ;
    SHAPE ABUTMENT ;
    PORT
      LAYER M4 ;
      RECT 0 197.04 0.024 197.064 ;
    END
  END r0_rd_out[88]
  PIN r0_rd_out[89]
    DIRECTION OUTPUT ;
    USE SIGNAL ;
    SHAPE ABUTMENT ;
    PORT
      LAYER M4 ;
      RECT 0 197.952 0.024 197.976 ;
    END
  END r0_rd_out[89]
  PIN r0_rd_out[90]
    DIRECTION OUTPUT ;
    USE SIGNAL ;
    SHAPE ABUTMENT ;
    PORT
      LAYER M4 ;
      RECT 0 198.864 0.024 198.888 ;
    END
  END r0_rd_out[90]
  PIN r0_rd_out[91]
    DIRECTION OUTPUT ;
    USE SIGNAL ;
    SHAPE ABUTMENT ;
    PORT
      LAYER M4 ;
      RECT 0 199.776 0.024 199.8 ;
    END
  END r0_rd_out[91]
  PIN r0_rd_out[92]
    DIRECTION OUTPUT ;
    USE SIGNAL ;
    SHAPE ABUTMENT ;
    PORT
      LAYER M4 ;
      RECT 0 200.688 0.024 200.712 ;
    END
  END r0_rd_out[92]
  PIN r0_rd_out[93]
    DIRECTION OUTPUT ;
    USE SIGNAL ;
    SHAPE ABUTMENT ;
    PORT
      LAYER M4 ;
      RECT 0 201.6 0.024 201.624 ;
    END
  END r0_rd_out[93]
  PIN r0_rd_out[94]
    DIRECTION OUTPUT ;
    USE SIGNAL ;
    SHAPE ABUTMENT ;
    PORT
      LAYER M4 ;
      RECT 0 202.512 0.024 202.536 ;
    END
  END r0_rd_out[94]
  PIN r0_rd_out[95]
    DIRECTION OUTPUT ;
    USE SIGNAL ;
    SHAPE ABUTMENT ;
    PORT
      LAYER M4 ;
      RECT 0 203.424 0.024 203.448 ;
    END
  END r0_rd_out[95]
  PIN r0_rd_out[96]
    DIRECTION OUTPUT ;
    USE SIGNAL ;
    SHAPE ABUTMENT ;
    PORT
      LAYER M4 ;
      RECT 0 204.336 0.024 204.36 ;
    END
  END r0_rd_out[96]
  PIN r0_rd_out[97]
    DIRECTION OUTPUT ;
    USE SIGNAL ;
    SHAPE ABUTMENT ;
    PORT
      LAYER M4 ;
      RECT 0 205.248 0.024 205.272 ;
    END
  END r0_rd_out[97]
  PIN r0_rd_out[98]
    DIRECTION OUTPUT ;
    USE SIGNAL ;
    SHAPE ABUTMENT ;
    PORT
      LAYER M4 ;
      RECT 0 206.16 0.024 206.184 ;
    END
  END r0_rd_out[98]
  PIN r0_rd_out[99]
    DIRECTION OUTPUT ;
    USE SIGNAL ;
    SHAPE ABUTMENT ;
    PORT
      LAYER M4 ;
      RECT 0 207.072 0.024 207.096 ;
    END
  END r0_rd_out[99]
  PIN r0_rd_out[100]
    DIRECTION OUTPUT ;
    USE SIGNAL ;
    SHAPE ABUTMENT ;
    PORT
      LAYER M4 ;
      RECT 0 207.984 0.024 208.008 ;
    END
  END r0_rd_out[100]
  PIN r0_rd_out[101]
    DIRECTION OUTPUT ;
    USE SIGNAL ;
    SHAPE ABUTMENT ;
    PORT
      LAYER M4 ;
      RECT 0 208.896 0.024 208.92 ;
    END
  END r0_rd_out[101]
  PIN r0_rd_out[102]
    DIRECTION OUTPUT ;
    USE SIGNAL ;
    SHAPE ABUTMENT ;
    PORT
      LAYER M4 ;
      RECT 0 209.808 0.024 209.832 ;
    END
  END r0_rd_out[102]
  PIN r0_rd_out[103]
    DIRECTION OUTPUT ;
    USE SIGNAL ;
    SHAPE ABUTMENT ;
    PORT
      LAYER M4 ;
      RECT 0 210.72 0.024 210.744 ;
    END
  END r0_rd_out[103]
  PIN r0_rd_out[104]
    DIRECTION OUTPUT ;
    USE SIGNAL ;
    SHAPE ABUTMENT ;
    PORT
      LAYER M4 ;
      RECT 0 211.632 0.024 211.656 ;
    END
  END r0_rd_out[104]
  PIN r0_rd_out[105]
    DIRECTION OUTPUT ;
    USE SIGNAL ;
    SHAPE ABUTMENT ;
    PORT
      LAYER M4 ;
      RECT 0 212.544 0.024 212.568 ;
    END
  END r0_rd_out[105]
  PIN r0_rd_out[106]
    DIRECTION OUTPUT ;
    USE SIGNAL ;
    SHAPE ABUTMENT ;
    PORT
      LAYER M4 ;
      RECT 0 213.456 0.024 213.48 ;
    END
  END r0_rd_out[106]
  PIN r0_rd_out[107]
    DIRECTION OUTPUT ;
    USE SIGNAL ;
    SHAPE ABUTMENT ;
    PORT
      LAYER M4 ;
      RECT 0 214.368 0.024 214.392 ;
    END
  END r0_rd_out[107]
  PIN r0_rd_out[108]
    DIRECTION OUTPUT ;
    USE SIGNAL ;
    SHAPE ABUTMENT ;
    PORT
      LAYER M4 ;
      RECT 0 215.28 0.024 215.304 ;
    END
  END r0_rd_out[108]
  PIN r0_rd_out[109]
    DIRECTION OUTPUT ;
    USE SIGNAL ;
    SHAPE ABUTMENT ;
    PORT
      LAYER M4 ;
      RECT 0 216.192 0.024 216.216 ;
    END
  END r0_rd_out[109]
  PIN r0_rd_out[110]
    DIRECTION OUTPUT ;
    USE SIGNAL ;
    SHAPE ABUTMENT ;
    PORT
      LAYER M4 ;
      RECT 0 217.104 0.024 217.128 ;
    END
  END r0_rd_out[110]
  PIN r0_rd_out[111]
    DIRECTION OUTPUT ;
    USE SIGNAL ;
    SHAPE ABUTMENT ;
    PORT
      LAYER M4 ;
      RECT 0 218.016 0.024 218.04 ;
    END
  END r0_rd_out[111]
  PIN r0_rd_out[112]
    DIRECTION OUTPUT ;
    USE SIGNAL ;
    SHAPE ABUTMENT ;
    PORT
      LAYER M4 ;
      RECT 0 218.928 0.024 218.952 ;
    END
  END r0_rd_out[112]
  PIN r0_rd_out[113]
    DIRECTION OUTPUT ;
    USE SIGNAL ;
    SHAPE ABUTMENT ;
    PORT
      LAYER M4 ;
      RECT 0 219.84 0.024 219.864 ;
    END
  END r0_rd_out[113]
  PIN r0_rd_out[114]
    DIRECTION OUTPUT ;
    USE SIGNAL ;
    SHAPE ABUTMENT ;
    PORT
      LAYER M4 ;
      RECT 0 220.752 0.024 220.776 ;
    END
  END r0_rd_out[114]
  PIN r0_rd_out[115]
    DIRECTION OUTPUT ;
    USE SIGNAL ;
    SHAPE ABUTMENT ;
    PORT
      LAYER M4 ;
      RECT 0 221.664 0.024 221.688 ;
    END
  END r0_rd_out[115]
  PIN r0_rd_out[116]
    DIRECTION OUTPUT ;
    USE SIGNAL ;
    SHAPE ABUTMENT ;
    PORT
      LAYER M4 ;
      RECT 0 222.576 0.024 222.6 ;
    END
  END r0_rd_out[116]
  PIN r0_rd_out[117]
    DIRECTION OUTPUT ;
    USE SIGNAL ;
    SHAPE ABUTMENT ;
    PORT
      LAYER M4 ;
      RECT 0 223.488 0.024 223.512 ;
    END
  END r0_rd_out[117]
  PIN r0_rd_out[118]
    DIRECTION OUTPUT ;
    USE SIGNAL ;
    SHAPE ABUTMENT ;
    PORT
      LAYER M4 ;
      RECT 0 224.4 0.024 224.424 ;
    END
  END r0_rd_out[118]
  PIN r0_rd_out[119]
    DIRECTION OUTPUT ;
    USE SIGNAL ;
    SHAPE ABUTMENT ;
    PORT
      LAYER M4 ;
      RECT 0 225.312 0.024 225.336 ;
    END
  END r0_rd_out[119]
  PIN r0_rd_out[120]
    DIRECTION OUTPUT ;
    USE SIGNAL ;
    SHAPE ABUTMENT ;
    PORT
      LAYER M4 ;
      RECT 0 226.224 0.024 226.248 ;
    END
  END r0_rd_out[120]
  PIN r0_rd_out[121]
    DIRECTION OUTPUT ;
    USE SIGNAL ;
    SHAPE ABUTMENT ;
    PORT
      LAYER M4 ;
      RECT 0 227.136 0.024 227.16 ;
    END
  END r0_rd_out[121]
  PIN r0_rd_out[122]
    DIRECTION OUTPUT ;
    USE SIGNAL ;
    SHAPE ABUTMENT ;
    PORT
      LAYER M4 ;
      RECT 0 228.048 0.024 228.072 ;
    END
  END r0_rd_out[122]
  PIN r0_rd_out[123]
    DIRECTION OUTPUT ;
    USE SIGNAL ;
    SHAPE ABUTMENT ;
    PORT
      LAYER M4 ;
      RECT 0 228.96 0.024 228.984 ;
    END
  END r0_rd_out[123]
  PIN r0_rd_out[124]
    DIRECTION OUTPUT ;
    USE SIGNAL ;
    SHAPE ABUTMENT ;
    PORT
      LAYER M4 ;
      RECT 0 229.872 0.024 229.896 ;
    END
  END r0_rd_out[124]
  PIN r0_rd_out[125]
    DIRECTION OUTPUT ;
    USE SIGNAL ;
    SHAPE ABUTMENT ;
    PORT
      LAYER M4 ;
      RECT 0 230.784 0.024 230.808 ;
    END
  END r0_rd_out[125]
  PIN r0_rd_out[126]
    DIRECTION OUTPUT ;
    USE SIGNAL ;
    SHAPE ABUTMENT ;
    PORT
      LAYER M4 ;
      RECT 0 231.696 0.024 231.72 ;
    END
  END r0_rd_out[126]
  PIN r0_rd_out[127]
    DIRECTION OUTPUT ;
    USE SIGNAL ;
    SHAPE ABUTMENT ;
    PORT
      LAYER M4 ;
      RECT 0 232.608 0.024 232.632 ;
    END
  END r0_rd_out[127]
  PIN w0_addr_in[0]
    DIRECTION INPUT ;
    USE SIGNAL ;
    SHAPE ABUTMENT ;
    PORT
      LAYER M4 ;
      RECT 0 233.52 0.024 233.544 ;
    END
  END w0_addr_in[0]
  PIN w0_addr_in[1]
    DIRECTION INPUT ;
    USE SIGNAL ;
    SHAPE ABUTMENT ;
    PORT
      LAYER M4 ;
      RECT 0 234.432 0.024 234.456 ;
    END
  END w0_addr_in[1]
  PIN w0_addr_in[2]
    DIRECTION INPUT ;
    USE SIGNAL ;
    SHAPE ABUTMENT ;
    PORT
      LAYER M4 ;
      RECT 0 235.344 0.024 235.368 ;
    END
  END w0_addr_in[2]
  PIN w0_addr_in[3]
    DIRECTION INPUT ;
    USE SIGNAL ;
    SHAPE ABUTMENT ;
    PORT
      LAYER M4 ;
      RECT 0 236.256 0.024 236.28 ;
    END
  END w0_addr_in[3]
  PIN w0_addr_in[4]
    DIRECTION INPUT ;
    USE SIGNAL ;
    SHAPE ABUTMENT ;
    PORT
      LAYER M4 ;
      RECT 0 237.168 0.024 237.192 ;
    END
  END w0_addr_in[4]
  PIN w0_addr_in[5]
    DIRECTION INPUT ;
    USE SIGNAL ;
    SHAPE ABUTMENT ;
    PORT
      LAYER M4 ;
      RECT 0 238.08 0.024 238.104 ;
    END
  END w0_addr_in[5]
  PIN w0_addr_in[6]
    DIRECTION INPUT ;
    USE SIGNAL ;
    SHAPE ABUTMENT ;
    PORT
      LAYER M4 ;
      RECT 0 238.992 0.024 239.016 ;
    END
  END w0_addr_in[6]
  PIN w0_addr_in[7]
    DIRECTION INPUT ;
    USE SIGNAL ;
    SHAPE ABUTMENT ;
    PORT
      LAYER M4 ;
      RECT 0 239.904 0.024 239.928 ;
    END
  END w0_addr_in[7]
  PIN w0_addr_in[8]
    DIRECTION INPUT ;
    USE SIGNAL ;
    SHAPE ABUTMENT ;
    PORT
      LAYER M4 ;
      RECT 0 240.816 0.024 240.84 ;
    END
  END w0_addr_in[8]
  PIN w0_addr_in[9]
    DIRECTION INPUT ;
    USE SIGNAL ;
    SHAPE ABUTMENT ;
    PORT
      LAYER M4 ;
      RECT 0 241.728 0.024 241.752 ;
    END
  END w0_addr_in[9]
  PIN w0_addr_in[10]
    DIRECTION INPUT ;
    USE SIGNAL ;
    SHAPE ABUTMENT ;
    PORT
      LAYER M4 ;
      RECT 0 242.64 0.024 242.664 ;
    END
  END w0_addr_in[10]
  PIN r0_addr_in[0]
    DIRECTION INPUT ;
    USE SIGNAL ;
    SHAPE ABUTMENT ;
    PORT
      LAYER M4 ;
      RECT 0 243.552 0.024 243.576 ;
    END
  END r0_addr_in[0]
  PIN r0_addr_in[1]
    DIRECTION INPUT ;
    USE SIGNAL ;
    SHAPE ABUTMENT ;
    PORT
      LAYER M4 ;
      RECT 0 244.464 0.024 244.488 ;
    END
  END r0_addr_in[1]
  PIN r0_addr_in[2]
    DIRECTION INPUT ;
    USE SIGNAL ;
    SHAPE ABUTMENT ;
    PORT
      LAYER M4 ;
      RECT 0 245.376 0.024 245.4 ;
    END
  END r0_addr_in[2]
  PIN r0_addr_in[3]
    DIRECTION INPUT ;
    USE SIGNAL ;
    SHAPE ABUTMENT ;
    PORT
      LAYER M4 ;
      RECT 0 246.288 0.024 246.312 ;
    END
  END r0_addr_in[3]
  PIN r0_addr_in[4]
    DIRECTION INPUT ;
    USE SIGNAL ;
    SHAPE ABUTMENT ;
    PORT
      LAYER M4 ;
      RECT 0 247.2 0.024 247.224 ;
    END
  END r0_addr_in[4]
  PIN r0_addr_in[5]
    DIRECTION INPUT ;
    USE SIGNAL ;
    SHAPE ABUTMENT ;
    PORT
      LAYER M4 ;
      RECT 0 248.112 0.024 248.136 ;
    END
  END r0_addr_in[5]
  PIN r0_addr_in[6]
    DIRECTION INPUT ;
    USE SIGNAL ;
    SHAPE ABUTMENT ;
    PORT
      LAYER M4 ;
      RECT 0 249.024 0.024 249.048 ;
    END
  END r0_addr_in[6]
  PIN r0_addr_in[7]
    DIRECTION INPUT ;
    USE SIGNAL ;
    SHAPE ABUTMENT ;
    PORT
      LAYER M4 ;
      RECT 0 249.936 0.024 249.96 ;
    END
  END r0_addr_in[7]
  PIN r0_addr_in[8]
    DIRECTION INPUT ;
    USE SIGNAL ;
    SHAPE ABUTMENT ;
    PORT
      LAYER M4 ;
      RECT 0 250.848 0.024 250.872 ;
    END
  END r0_addr_in[8]
  PIN r0_addr_in[9]
    DIRECTION INPUT ;
    USE SIGNAL ;
    SHAPE ABUTMENT ;
    PORT
      LAYER M4 ;
      RECT 0 251.76 0.024 251.784 ;
    END
  END r0_addr_in[9]
  PIN r0_addr_in[10]
    DIRECTION INPUT ;
    USE SIGNAL ;
    SHAPE ABUTMENT ;
    PORT
      LAYER M4 ;
      RECT 0 252.672 0.024 252.696 ;
    END
  END r0_addr_in[10]
  PIN w0_we_in
    DIRECTION INPUT ;
    USE SIGNAL ;
    SHAPE ABUTMENT ;
    PORT
      LAYER M4 ;
      RECT 0 253.584 0.024 253.608 ;
    END
  END w0_we_in
  PIN w0_ce_in
    DIRECTION INPUT ;
    USE SIGNAL ;
    SHAPE ABUTMENT ;
    PORT
      LAYER M4 ;
      RECT 0 254.496 0.024 254.52 ;
    END
  END w0_ce_in
  PIN w0_clk
    DIRECTION INPUT ;
    USE SIGNAL ;
    SHAPE ABUTMENT ;
    PORT
      LAYER M4 ;
      RECT 0 255.408 0.024 255.432 ;
    END
  END w0_clk
  PIN r0_ce_in
    DIRECTION INPUT ;
    USE SIGNAL ;
    SHAPE ABUTMENT ;
    PORT
      LAYER M4 ;
      RECT 0 256.32 0.024 256.344 ;
    END
  END r0_ce_in
  PIN r0_clk
    DIRECTION INPUT ;
    USE SIGNAL ;
    SHAPE ABUTMENT ;
    PORT
      LAYER M4 ;
      RECT 0 257.232 0.024 257.256 ;
    END
  END r0_clk
  PIN VSS
    DIRECTION INOUT ;
    USE GROUND ;
    PORT
      LAYER M4 ;
      RECT 0.048 0 51.378 0.096 ;
      RECT 0.048 0.768 51.378 0.864 ;
      RECT 0.048 1.536 51.378 1.632 ;
      RECT 0.048 2.304 51.378 2.4 ;
      RECT 0.048 3.072 51.378 3.168 ;
      RECT 0.048 3.84 51.378 3.936 ;
      RECT 0.048 4.608 51.378 4.704 ;
      RECT 0.048 5.376 51.378 5.472 ;
      RECT 0.048 6.144 51.378 6.24 ;
      RECT 0.048 6.912 51.378 7.008 ;
      RECT 0.048 7.68 51.378 7.776 ;
      RECT 0.048 8.448 51.378 8.544 ;
      RECT 0.048 9.216 51.378 9.312 ;
      RECT 0.048 9.984 51.378 10.08 ;
      RECT 0.048 10.752 51.378 10.848 ;
      RECT 0.048 11.52 51.378 11.616 ;
      RECT 0.048 12.288 51.378 12.384 ;
      RECT 0.048 13.056 51.378 13.152 ;
      RECT 0.048 13.824 51.378 13.92 ;
      RECT 0.048 14.592 51.378 14.688 ;
      RECT 0.048 15.36 51.378 15.456 ;
      RECT 0.048 16.128 51.378 16.224 ;
      RECT 0.048 16.896 51.378 16.992 ;
      RECT 0.048 17.664 51.378 17.76 ;
      RECT 0.048 18.432 51.378 18.528 ;
      RECT 0.048 19.2 51.378 19.296 ;
      RECT 0.048 19.968 51.378 20.064 ;
      RECT 0.048 20.736 51.378 20.832 ;
      RECT 0.048 21.504 51.378 21.6 ;
      RECT 0.048 22.272 51.378 22.368 ;
      RECT 0.048 23.04 51.378 23.136 ;
      RECT 0.048 23.808 51.378 23.904 ;
      RECT 0.048 24.576 51.378 24.672 ;
      RECT 0.048 25.344 51.378 25.44 ;
      RECT 0.048 26.112 51.378 26.208 ;
      RECT 0.048 26.88 51.378 26.976 ;
      RECT 0.048 27.648 51.378 27.744 ;
      RECT 0.048 28.416 51.378 28.512 ;
      RECT 0.048 29.184 51.378 29.28 ;
      RECT 0.048 29.952 51.378 30.048 ;
      RECT 0.048 30.72 51.378 30.816 ;
      RECT 0.048 31.488 51.378 31.584 ;
      RECT 0.048 32.256 51.378 32.352 ;
      RECT 0.048 33.024 51.378 33.12 ;
      RECT 0.048 33.792 51.378 33.888 ;
      RECT 0.048 34.56 51.378 34.656 ;
      RECT 0.048 35.328 51.378 35.424 ;
      RECT 0.048 36.096 51.378 36.192 ;
      RECT 0.048 36.864 51.378 36.96 ;
      RECT 0.048 37.632 51.378 37.728 ;
      RECT 0.048 38.4 51.378 38.496 ;
      RECT 0.048 39.168 51.378 39.264 ;
      RECT 0.048 39.936 51.378 40.032 ;
      RECT 0.048 40.704 51.378 40.8 ;
      RECT 0.048 41.472 51.378 41.568 ;
      RECT 0.048 42.24 51.378 42.336 ;
      RECT 0.048 43.008 51.378 43.104 ;
      RECT 0.048 43.776 51.378 43.872 ;
      RECT 0.048 44.544 51.378 44.64 ;
      RECT 0.048 45.312 51.378 45.408 ;
      RECT 0.048 46.08 51.378 46.176 ;
      RECT 0.048 46.848 51.378 46.944 ;
      RECT 0.048 47.616 51.378 47.712 ;
      RECT 0.048 48.384 51.378 48.48 ;
      RECT 0.048 49.152 51.378 49.248 ;
      RECT 0.048 49.92 51.378 50.016 ;
      RECT 0.048 50.688 51.378 50.784 ;
      RECT 0.048 51.456 51.378 51.552 ;
      RECT 0.048 52.224 51.378 52.32 ;
      RECT 0.048 52.992 51.378 53.088 ;
      RECT 0.048 53.76 51.378 53.856 ;
      RECT 0.048 54.528 51.378 54.624 ;
      RECT 0.048 55.296 51.378 55.392 ;
      RECT 0.048 56.064 51.378 56.16 ;
      RECT 0.048 56.832 51.378 56.928 ;
      RECT 0.048 57.6 51.378 57.696 ;
      RECT 0.048 58.368 51.378 58.464 ;
      RECT 0.048 59.136 51.378 59.232 ;
      RECT 0.048 59.904 51.378 60 ;
      RECT 0.048 60.672 51.378 60.768 ;
      RECT 0.048 61.44 51.378 61.536 ;
      RECT 0.048 62.208 51.378 62.304 ;
      RECT 0.048 62.976 51.378 63.072 ;
      RECT 0.048 63.744 51.378 63.84 ;
      RECT 0.048 64.512 51.378 64.608 ;
      RECT 0.048 65.28 51.378 65.376 ;
      RECT 0.048 66.048 51.378 66.144 ;
      RECT 0.048 66.816 51.378 66.912 ;
      RECT 0.048 67.584 51.378 67.68 ;
      RECT 0.048 68.352 51.378 68.448 ;
      RECT 0.048 69.12 51.378 69.216 ;
      RECT 0.048 69.888 51.378 69.984 ;
      RECT 0.048 70.656 51.378 70.752 ;
      RECT 0.048 71.424 51.378 71.52 ;
      RECT 0.048 72.192 51.378 72.288 ;
      RECT 0.048 72.96 51.378 73.056 ;
      RECT 0.048 73.728 51.378 73.824 ;
      RECT 0.048 74.496 51.378 74.592 ;
      RECT 0.048 75.264 51.378 75.36 ;
      RECT 0.048 76.032 51.378 76.128 ;
      RECT 0.048 76.8 51.378 76.896 ;
      RECT 0.048 77.568 51.378 77.664 ;
      RECT 0.048 78.336 51.378 78.432 ;
      RECT 0.048 79.104 51.378 79.2 ;
      RECT 0.048 79.872 51.378 79.968 ;
      RECT 0.048 80.64 51.378 80.736 ;
      RECT 0.048 81.408 51.378 81.504 ;
      RECT 0.048 82.176 51.378 82.272 ;
      RECT 0.048 82.944 51.378 83.04 ;
      RECT 0.048 83.712 51.378 83.808 ;
      RECT 0.048 84.48 51.378 84.576 ;
      RECT 0.048 85.248 51.378 85.344 ;
      RECT 0.048 86.016 51.378 86.112 ;
      RECT 0.048 86.784 51.378 86.88 ;
      RECT 0.048 87.552 51.378 87.648 ;
      RECT 0.048 88.32 51.378 88.416 ;
      RECT 0.048 89.088 51.378 89.184 ;
      RECT 0.048 89.856 51.378 89.952 ;
      RECT 0.048 90.624 51.378 90.72 ;
      RECT 0.048 91.392 51.378 91.488 ;
      RECT 0.048 92.16 51.378 92.256 ;
      RECT 0.048 92.928 51.378 93.024 ;
      RECT 0.048 93.696 51.378 93.792 ;
      RECT 0.048 94.464 51.378 94.56 ;
      RECT 0.048 95.232 51.378 95.328 ;
      RECT 0.048 96 51.378 96.096 ;
      RECT 0.048 96.768 51.378 96.864 ;
      RECT 0.048 97.536 51.378 97.632 ;
      RECT 0.048 98.304 51.378 98.4 ;
      RECT 0.048 99.072 51.378 99.168 ;
      RECT 0.048 99.84 51.378 99.936 ;
      RECT 0.048 100.608 51.378 100.704 ;
      RECT 0.048 101.376 51.378 101.472 ;
      RECT 0.048 102.144 51.378 102.24 ;
      RECT 0.048 102.912 51.378 103.008 ;
      RECT 0.048 103.68 51.378 103.776 ;
      RECT 0.048 104.448 51.378 104.544 ;
      RECT 0.048 105.216 51.378 105.312 ;
      RECT 0.048 105.984 51.378 106.08 ;
      RECT 0.048 106.752 51.378 106.848 ;
      RECT 0.048 107.52 51.378 107.616 ;
      RECT 0.048 108.288 51.378 108.384 ;
      RECT 0.048 109.056 51.378 109.152 ;
      RECT 0.048 109.824 51.378 109.92 ;
      RECT 0.048 110.592 51.378 110.688 ;
      RECT 0.048 111.36 51.378 111.456 ;
      RECT 0.048 112.128 51.378 112.224 ;
      RECT 0.048 112.896 51.378 112.992 ;
      RECT 0.048 113.664 51.378 113.76 ;
      RECT 0.048 114.432 51.378 114.528 ;
      RECT 0.048 115.2 51.378 115.296 ;
      RECT 0.048 115.968 51.378 116.064 ;
      RECT 0.048 116.736 51.378 116.832 ;
      RECT 0.048 117.504 51.378 117.6 ;
      RECT 0.048 118.272 51.378 118.368 ;
      RECT 0.048 119.04 51.378 119.136 ;
      RECT 0.048 119.808 51.378 119.904 ;
      RECT 0.048 120.576 51.378 120.672 ;
      RECT 0.048 121.344 51.378 121.44 ;
      RECT 0.048 122.112 51.378 122.208 ;
      RECT 0.048 122.88 51.378 122.976 ;
      RECT 0.048 123.648 51.378 123.744 ;
      RECT 0.048 124.416 51.378 124.512 ;
      RECT 0.048 125.184 51.378 125.28 ;
      RECT 0.048 125.952 51.378 126.048 ;
      RECT 0.048 126.72 51.378 126.816 ;
      RECT 0.048 127.488 51.378 127.584 ;
      RECT 0.048 128.256 51.378 128.352 ;
      RECT 0.048 129.024 51.378 129.12 ;
      RECT 0.048 129.792 51.378 129.888 ;
      RECT 0.048 130.56 51.378 130.656 ;
      RECT 0.048 131.328 51.378 131.424 ;
      RECT 0.048 132.096 51.378 132.192 ;
      RECT 0.048 132.864 51.378 132.96 ;
      RECT 0.048 133.632 51.378 133.728 ;
      RECT 0.048 134.4 51.378 134.496 ;
      RECT 0.048 135.168 51.378 135.264 ;
      RECT 0.048 135.936 51.378 136.032 ;
      RECT 0.048 136.704 51.378 136.8 ;
      RECT 0.048 137.472 51.378 137.568 ;
      RECT 0.048 138.24 51.378 138.336 ;
      RECT 0.048 139.008 51.378 139.104 ;
      RECT 0.048 139.776 51.378 139.872 ;
      RECT 0.048 140.544 51.378 140.64 ;
      RECT 0.048 141.312 51.378 141.408 ;
      RECT 0.048 142.08 51.378 142.176 ;
      RECT 0.048 142.848 51.378 142.944 ;
      RECT 0.048 143.616 51.378 143.712 ;
      RECT 0.048 144.384 51.378 144.48 ;
      RECT 0.048 145.152 51.378 145.248 ;
      RECT 0.048 145.92 51.378 146.016 ;
      RECT 0.048 146.688 51.378 146.784 ;
      RECT 0.048 147.456 51.378 147.552 ;
      RECT 0.048 148.224 51.378 148.32 ;
      RECT 0.048 148.992 51.378 149.088 ;
      RECT 0.048 149.76 51.378 149.856 ;
      RECT 0.048 150.528 51.378 150.624 ;
      RECT 0.048 151.296 51.378 151.392 ;
      RECT 0.048 152.064 51.378 152.16 ;
      RECT 0.048 152.832 51.378 152.928 ;
      RECT 0.048 153.6 51.378 153.696 ;
      RECT 0.048 154.368 51.378 154.464 ;
      RECT 0.048 155.136 51.378 155.232 ;
      RECT 0.048 155.904 51.378 156 ;
      RECT 0.048 156.672 51.378 156.768 ;
      RECT 0.048 157.44 51.378 157.536 ;
      RECT 0.048 158.208 51.378 158.304 ;
      RECT 0.048 158.976 51.378 159.072 ;
      RECT 0.048 159.744 51.378 159.84 ;
      RECT 0.048 160.512 51.378 160.608 ;
      RECT 0.048 161.28 51.378 161.376 ;
      RECT 0.048 162.048 51.378 162.144 ;
      RECT 0.048 162.816 51.378 162.912 ;
      RECT 0.048 163.584 51.378 163.68 ;
      RECT 0.048 164.352 51.378 164.448 ;
      RECT 0.048 165.12 51.378 165.216 ;
      RECT 0.048 165.888 51.378 165.984 ;
      RECT 0.048 166.656 51.378 166.752 ;
      RECT 0.048 167.424 51.378 167.52 ;
      RECT 0.048 168.192 51.378 168.288 ;
      RECT 0.048 168.96 51.378 169.056 ;
      RECT 0.048 169.728 51.378 169.824 ;
      RECT 0.048 170.496 51.378 170.592 ;
      RECT 0.048 171.264 51.378 171.36 ;
      RECT 0.048 172.032 51.378 172.128 ;
      RECT 0.048 172.8 51.378 172.896 ;
      RECT 0.048 173.568 51.378 173.664 ;
      RECT 0.048 174.336 51.378 174.432 ;
      RECT 0.048 175.104 51.378 175.2 ;
      RECT 0.048 175.872 51.378 175.968 ;
      RECT 0.048 176.64 51.378 176.736 ;
      RECT 0.048 177.408 51.378 177.504 ;
      RECT 0.048 178.176 51.378 178.272 ;
      RECT 0.048 178.944 51.378 179.04 ;
      RECT 0.048 179.712 51.378 179.808 ;
      RECT 0.048 180.48 51.378 180.576 ;
      RECT 0.048 181.248 51.378 181.344 ;
      RECT 0.048 182.016 51.378 182.112 ;
      RECT 0.048 182.784 51.378 182.88 ;
      RECT 0.048 183.552 51.378 183.648 ;
      RECT 0.048 184.32 51.378 184.416 ;
      RECT 0.048 185.088 51.378 185.184 ;
      RECT 0.048 185.856 51.378 185.952 ;
      RECT 0.048 186.624 51.378 186.72 ;
      RECT 0.048 187.392 51.378 187.488 ;
      RECT 0.048 188.16 51.378 188.256 ;
      RECT 0.048 188.928 51.378 189.024 ;
      RECT 0.048 189.696 51.378 189.792 ;
      RECT 0.048 190.464 51.378 190.56 ;
      RECT 0.048 191.232 51.378 191.328 ;
      RECT 0.048 192 51.378 192.096 ;
      RECT 0.048 192.768 51.378 192.864 ;
      RECT 0.048 193.536 51.378 193.632 ;
      RECT 0.048 194.304 51.378 194.4 ;
      RECT 0.048 195.072 51.378 195.168 ;
      RECT 0.048 195.84 51.378 195.936 ;
      RECT 0.048 196.608 51.378 196.704 ;
      RECT 0.048 197.376 51.378 197.472 ;
      RECT 0.048 198.144 51.378 198.24 ;
      RECT 0.048 198.912 51.378 199.008 ;
      RECT 0.048 199.68 51.378 199.776 ;
      RECT 0.048 200.448 51.378 200.544 ;
      RECT 0.048 201.216 51.378 201.312 ;
      RECT 0.048 201.984 51.378 202.08 ;
      RECT 0.048 202.752 51.378 202.848 ;
      RECT 0.048 203.52 51.378 203.616 ;
      RECT 0.048 204.288 51.378 204.384 ;
      RECT 0.048 205.056 51.378 205.152 ;
      RECT 0.048 205.824 51.378 205.92 ;
      RECT 0.048 206.592 51.378 206.688 ;
      RECT 0.048 207.36 51.378 207.456 ;
      RECT 0.048 208.128 51.378 208.224 ;
      RECT 0.048 208.896 51.378 208.992 ;
      RECT 0.048 209.664 51.378 209.76 ;
      RECT 0.048 210.432 51.378 210.528 ;
      RECT 0.048 211.2 51.378 211.296 ;
      RECT 0.048 211.968 51.378 212.064 ;
      RECT 0.048 212.736 51.378 212.832 ;
      RECT 0.048 213.504 51.378 213.6 ;
      RECT 0.048 214.272 51.378 214.368 ;
      RECT 0.048 215.04 51.378 215.136 ;
      RECT 0.048 215.808 51.378 215.904 ;
      RECT 0.048 216.576 51.378 216.672 ;
      RECT 0.048 217.344 51.378 217.44 ;
      RECT 0.048 218.112 51.378 218.208 ;
      RECT 0.048 218.88 51.378 218.976 ;
      RECT 0.048 219.648 51.378 219.744 ;
      RECT 0.048 220.416 51.378 220.512 ;
      RECT 0.048 221.184 51.378 221.28 ;
      RECT 0.048 221.952 51.378 222.048 ;
      RECT 0.048 222.72 51.378 222.816 ;
      RECT 0.048 223.488 51.378 223.584 ;
      RECT 0.048 224.256 51.378 224.352 ;
      RECT 0.048 225.024 51.378 225.12 ;
      RECT 0.048 225.792 51.378 225.888 ;
      RECT 0.048 226.56 51.378 226.656 ;
      RECT 0.048 227.328 51.378 227.424 ;
      RECT 0.048 228.096 51.378 228.192 ;
      RECT 0.048 228.864 51.378 228.96 ;
      RECT 0.048 229.632 51.378 229.728 ;
      RECT 0.048 230.4 51.378 230.496 ;
      RECT 0.048 231.168 51.378 231.264 ;
      RECT 0.048 231.936 51.378 232.032 ;
      RECT 0.048 232.704 51.378 232.8 ;
      RECT 0.048 233.472 51.378 233.568 ;
      RECT 0.048 234.24 51.378 234.336 ;
      RECT 0.048 235.008 51.378 235.104 ;
      RECT 0.048 235.776 51.378 235.872 ;
      RECT 0.048 236.544 51.378 236.64 ;
      RECT 0.048 237.312 51.378 237.408 ;
      RECT 0.048 238.08 51.378 238.176 ;
      RECT 0.048 238.848 51.378 238.944 ;
      RECT 0.048 239.616 51.378 239.712 ;
      RECT 0.048 240.384 51.378 240.48 ;
      RECT 0.048 241.152 51.378 241.248 ;
      RECT 0.048 241.92 51.378 242.016 ;
      RECT 0.048 242.688 51.378 242.784 ;
      RECT 0.048 243.456 51.378 243.552 ;
      RECT 0.048 244.224 51.378 244.32 ;
      RECT 0.048 244.992 51.378 245.088 ;
      RECT 0.048 245.76 51.378 245.856 ;
      RECT 0.048 246.528 51.378 246.624 ;
      RECT 0.048 247.296 51.378 247.392 ;
      RECT 0.048 248.064 51.378 248.16 ;
      RECT 0.048 248.832 51.378 248.928 ;
      RECT 0.048 249.6 51.378 249.696 ;
      RECT 0.048 250.368 51.378 250.464 ;
      RECT 0.048 251.136 51.378 251.232 ;
      RECT 0.048 251.904 51.378 252 ;
      RECT 0.048 252.672 51.378 252.768 ;
      RECT 0.048 253.44 51.378 253.536 ;
      RECT 0.048 254.208 51.378 254.304 ;
      RECT 0.048 254.976 51.378 255.072 ;
      RECT 0.048 255.744 51.378 255.84 ;
      RECT 0.048 256.512 51.378 256.608 ;
      RECT 0.048 257.28 51.378 257.376 ;
      RECT 0.048 258.048 51.378 258.144 ;
      RECT 0.048 258.816 51.378 258.912 ;
      RECT 0.048 259.584 51.378 259.68 ;
      RECT 0.048 260.352 51.378 260.448 ;
      RECT 0.048 261.12 51.378 261.216 ;
      RECT 0.048 261.888 51.378 261.984 ;
      RECT 0.048 262.656 51.378 262.752 ;
      RECT 0.048 263.424 51.378 263.52 ;
      RECT 0.048 264.192 51.378 264.288 ;
      RECT 0.048 264.96 51.378 265.056 ;
    END
  END VSS
  PIN VDD
    DIRECTION INOUT ;
    USE POWER ;
    PORT
      LAYER M4 ;
      RECT 0.048 0.384 51.378 0.48 ;
      RECT 0.048 1.152 51.378 1.248 ;
      RECT 0.048 1.92 51.378 2.016 ;
      RECT 0.048 2.688 51.378 2.784 ;
      RECT 0.048 3.456 51.378 3.552 ;
      RECT 0.048 4.224 51.378 4.32 ;
      RECT 0.048 4.992 51.378 5.088 ;
      RECT 0.048 5.76 51.378 5.856 ;
      RECT 0.048 6.528 51.378 6.624 ;
      RECT 0.048 7.296 51.378 7.392 ;
      RECT 0.048 8.064 51.378 8.16 ;
      RECT 0.048 8.832 51.378 8.928 ;
      RECT 0.048 9.6 51.378 9.696 ;
      RECT 0.048 10.368 51.378 10.464 ;
      RECT 0.048 11.136 51.378 11.232 ;
      RECT 0.048 11.904 51.378 12 ;
      RECT 0.048 12.672 51.378 12.768 ;
      RECT 0.048 13.44 51.378 13.536 ;
      RECT 0.048 14.208 51.378 14.304 ;
      RECT 0.048 14.976 51.378 15.072 ;
      RECT 0.048 15.744 51.378 15.84 ;
      RECT 0.048 16.512 51.378 16.608 ;
      RECT 0.048 17.28 51.378 17.376 ;
      RECT 0.048 18.048 51.378 18.144 ;
      RECT 0.048 18.816 51.378 18.912 ;
      RECT 0.048 19.584 51.378 19.68 ;
      RECT 0.048 20.352 51.378 20.448 ;
      RECT 0.048 21.12 51.378 21.216 ;
      RECT 0.048 21.888 51.378 21.984 ;
      RECT 0.048 22.656 51.378 22.752 ;
      RECT 0.048 23.424 51.378 23.52 ;
      RECT 0.048 24.192 51.378 24.288 ;
      RECT 0.048 24.96 51.378 25.056 ;
      RECT 0.048 25.728 51.378 25.824 ;
      RECT 0.048 26.496 51.378 26.592 ;
      RECT 0.048 27.264 51.378 27.36 ;
      RECT 0.048 28.032 51.378 28.128 ;
      RECT 0.048 28.8 51.378 28.896 ;
      RECT 0.048 29.568 51.378 29.664 ;
      RECT 0.048 30.336 51.378 30.432 ;
      RECT 0.048 31.104 51.378 31.2 ;
      RECT 0.048 31.872 51.378 31.968 ;
      RECT 0.048 32.64 51.378 32.736 ;
      RECT 0.048 33.408 51.378 33.504 ;
      RECT 0.048 34.176 51.378 34.272 ;
      RECT 0.048 34.944 51.378 35.04 ;
      RECT 0.048 35.712 51.378 35.808 ;
      RECT 0.048 36.48 51.378 36.576 ;
      RECT 0.048 37.248 51.378 37.344 ;
      RECT 0.048 38.016 51.378 38.112 ;
      RECT 0.048 38.784 51.378 38.88 ;
      RECT 0.048 39.552 51.378 39.648 ;
      RECT 0.048 40.32 51.378 40.416 ;
      RECT 0.048 41.088 51.378 41.184 ;
      RECT 0.048 41.856 51.378 41.952 ;
      RECT 0.048 42.624 51.378 42.72 ;
      RECT 0.048 43.392 51.378 43.488 ;
      RECT 0.048 44.16 51.378 44.256 ;
      RECT 0.048 44.928 51.378 45.024 ;
      RECT 0.048 45.696 51.378 45.792 ;
      RECT 0.048 46.464 51.378 46.56 ;
      RECT 0.048 47.232 51.378 47.328 ;
      RECT 0.048 48 51.378 48.096 ;
      RECT 0.048 48.768 51.378 48.864 ;
      RECT 0.048 49.536 51.378 49.632 ;
      RECT 0.048 50.304 51.378 50.4 ;
      RECT 0.048 51.072 51.378 51.168 ;
      RECT 0.048 51.84 51.378 51.936 ;
      RECT 0.048 52.608 51.378 52.704 ;
      RECT 0.048 53.376 51.378 53.472 ;
      RECT 0.048 54.144 51.378 54.24 ;
      RECT 0.048 54.912 51.378 55.008 ;
      RECT 0.048 55.68 51.378 55.776 ;
      RECT 0.048 56.448 51.378 56.544 ;
      RECT 0.048 57.216 51.378 57.312 ;
      RECT 0.048 57.984 51.378 58.08 ;
      RECT 0.048 58.752 51.378 58.848 ;
      RECT 0.048 59.52 51.378 59.616 ;
      RECT 0.048 60.288 51.378 60.384 ;
      RECT 0.048 61.056 51.378 61.152 ;
      RECT 0.048 61.824 51.378 61.92 ;
      RECT 0.048 62.592 51.378 62.688 ;
      RECT 0.048 63.36 51.378 63.456 ;
      RECT 0.048 64.128 51.378 64.224 ;
      RECT 0.048 64.896 51.378 64.992 ;
      RECT 0.048 65.664 51.378 65.76 ;
      RECT 0.048 66.432 51.378 66.528 ;
      RECT 0.048 67.2 51.378 67.296 ;
      RECT 0.048 67.968 51.378 68.064 ;
      RECT 0.048 68.736 51.378 68.832 ;
      RECT 0.048 69.504 51.378 69.6 ;
      RECT 0.048 70.272 51.378 70.368 ;
      RECT 0.048 71.04 51.378 71.136 ;
      RECT 0.048 71.808 51.378 71.904 ;
      RECT 0.048 72.576 51.378 72.672 ;
      RECT 0.048 73.344 51.378 73.44 ;
      RECT 0.048 74.112 51.378 74.208 ;
      RECT 0.048 74.88 51.378 74.976 ;
      RECT 0.048 75.648 51.378 75.744 ;
      RECT 0.048 76.416 51.378 76.512 ;
      RECT 0.048 77.184 51.378 77.28 ;
      RECT 0.048 77.952 51.378 78.048 ;
      RECT 0.048 78.72 51.378 78.816 ;
      RECT 0.048 79.488 51.378 79.584 ;
      RECT 0.048 80.256 51.378 80.352 ;
      RECT 0.048 81.024 51.378 81.12 ;
      RECT 0.048 81.792 51.378 81.888 ;
      RECT 0.048 82.56 51.378 82.656 ;
      RECT 0.048 83.328 51.378 83.424 ;
      RECT 0.048 84.096 51.378 84.192 ;
      RECT 0.048 84.864 51.378 84.96 ;
      RECT 0.048 85.632 51.378 85.728 ;
      RECT 0.048 86.4 51.378 86.496 ;
      RECT 0.048 87.168 51.378 87.264 ;
      RECT 0.048 87.936 51.378 88.032 ;
      RECT 0.048 88.704 51.378 88.8 ;
      RECT 0.048 89.472 51.378 89.568 ;
      RECT 0.048 90.24 51.378 90.336 ;
      RECT 0.048 91.008 51.378 91.104 ;
      RECT 0.048 91.776 51.378 91.872 ;
      RECT 0.048 92.544 51.378 92.64 ;
      RECT 0.048 93.312 51.378 93.408 ;
      RECT 0.048 94.08 51.378 94.176 ;
      RECT 0.048 94.848 51.378 94.944 ;
      RECT 0.048 95.616 51.378 95.712 ;
      RECT 0.048 96.384 51.378 96.48 ;
      RECT 0.048 97.152 51.378 97.248 ;
      RECT 0.048 97.92 51.378 98.016 ;
      RECT 0.048 98.688 51.378 98.784 ;
      RECT 0.048 99.456 51.378 99.552 ;
      RECT 0.048 100.224 51.378 100.32 ;
      RECT 0.048 100.992 51.378 101.088 ;
      RECT 0.048 101.76 51.378 101.856 ;
      RECT 0.048 102.528 51.378 102.624 ;
      RECT 0.048 103.296 51.378 103.392 ;
      RECT 0.048 104.064 51.378 104.16 ;
      RECT 0.048 104.832 51.378 104.928 ;
      RECT 0.048 105.6 51.378 105.696 ;
      RECT 0.048 106.368 51.378 106.464 ;
      RECT 0.048 107.136 51.378 107.232 ;
      RECT 0.048 107.904 51.378 108 ;
      RECT 0.048 108.672 51.378 108.768 ;
      RECT 0.048 109.44 51.378 109.536 ;
      RECT 0.048 110.208 51.378 110.304 ;
      RECT 0.048 110.976 51.378 111.072 ;
      RECT 0.048 111.744 51.378 111.84 ;
      RECT 0.048 112.512 51.378 112.608 ;
      RECT 0.048 113.28 51.378 113.376 ;
      RECT 0.048 114.048 51.378 114.144 ;
      RECT 0.048 114.816 51.378 114.912 ;
      RECT 0.048 115.584 51.378 115.68 ;
      RECT 0.048 116.352 51.378 116.448 ;
      RECT 0.048 117.12 51.378 117.216 ;
      RECT 0.048 117.888 51.378 117.984 ;
      RECT 0.048 118.656 51.378 118.752 ;
      RECT 0.048 119.424 51.378 119.52 ;
      RECT 0.048 120.192 51.378 120.288 ;
      RECT 0.048 120.96 51.378 121.056 ;
      RECT 0.048 121.728 51.378 121.824 ;
      RECT 0.048 122.496 51.378 122.592 ;
      RECT 0.048 123.264 51.378 123.36 ;
      RECT 0.048 124.032 51.378 124.128 ;
      RECT 0.048 124.8 51.378 124.896 ;
      RECT 0.048 125.568 51.378 125.664 ;
      RECT 0.048 126.336 51.378 126.432 ;
      RECT 0.048 127.104 51.378 127.2 ;
      RECT 0.048 127.872 51.378 127.968 ;
      RECT 0.048 128.64 51.378 128.736 ;
      RECT 0.048 129.408 51.378 129.504 ;
      RECT 0.048 130.176 51.378 130.272 ;
      RECT 0.048 130.944 51.378 131.04 ;
      RECT 0.048 131.712 51.378 131.808 ;
      RECT 0.048 132.48 51.378 132.576 ;
      RECT 0.048 133.248 51.378 133.344 ;
      RECT 0.048 134.016 51.378 134.112 ;
      RECT 0.048 134.784 51.378 134.88 ;
      RECT 0.048 135.552 51.378 135.648 ;
      RECT 0.048 136.32 51.378 136.416 ;
      RECT 0.048 137.088 51.378 137.184 ;
      RECT 0.048 137.856 51.378 137.952 ;
      RECT 0.048 138.624 51.378 138.72 ;
      RECT 0.048 139.392 51.378 139.488 ;
      RECT 0.048 140.16 51.378 140.256 ;
      RECT 0.048 140.928 51.378 141.024 ;
      RECT 0.048 141.696 51.378 141.792 ;
      RECT 0.048 142.464 51.378 142.56 ;
      RECT 0.048 143.232 51.378 143.328 ;
      RECT 0.048 144 51.378 144.096 ;
      RECT 0.048 144.768 51.378 144.864 ;
      RECT 0.048 145.536 51.378 145.632 ;
      RECT 0.048 146.304 51.378 146.4 ;
      RECT 0.048 147.072 51.378 147.168 ;
      RECT 0.048 147.84 51.378 147.936 ;
      RECT 0.048 148.608 51.378 148.704 ;
      RECT 0.048 149.376 51.378 149.472 ;
      RECT 0.048 150.144 51.378 150.24 ;
      RECT 0.048 150.912 51.378 151.008 ;
      RECT 0.048 151.68 51.378 151.776 ;
      RECT 0.048 152.448 51.378 152.544 ;
      RECT 0.048 153.216 51.378 153.312 ;
      RECT 0.048 153.984 51.378 154.08 ;
      RECT 0.048 154.752 51.378 154.848 ;
      RECT 0.048 155.52 51.378 155.616 ;
      RECT 0.048 156.288 51.378 156.384 ;
      RECT 0.048 157.056 51.378 157.152 ;
      RECT 0.048 157.824 51.378 157.92 ;
      RECT 0.048 158.592 51.378 158.688 ;
      RECT 0.048 159.36 51.378 159.456 ;
      RECT 0.048 160.128 51.378 160.224 ;
      RECT 0.048 160.896 51.378 160.992 ;
      RECT 0.048 161.664 51.378 161.76 ;
      RECT 0.048 162.432 51.378 162.528 ;
      RECT 0.048 163.2 51.378 163.296 ;
      RECT 0.048 163.968 51.378 164.064 ;
      RECT 0.048 164.736 51.378 164.832 ;
      RECT 0.048 165.504 51.378 165.6 ;
      RECT 0.048 166.272 51.378 166.368 ;
      RECT 0.048 167.04 51.378 167.136 ;
      RECT 0.048 167.808 51.378 167.904 ;
      RECT 0.048 168.576 51.378 168.672 ;
      RECT 0.048 169.344 51.378 169.44 ;
      RECT 0.048 170.112 51.378 170.208 ;
      RECT 0.048 170.88 51.378 170.976 ;
      RECT 0.048 171.648 51.378 171.744 ;
      RECT 0.048 172.416 51.378 172.512 ;
      RECT 0.048 173.184 51.378 173.28 ;
      RECT 0.048 173.952 51.378 174.048 ;
      RECT 0.048 174.72 51.378 174.816 ;
      RECT 0.048 175.488 51.378 175.584 ;
      RECT 0.048 176.256 51.378 176.352 ;
      RECT 0.048 177.024 51.378 177.12 ;
      RECT 0.048 177.792 51.378 177.888 ;
      RECT 0.048 178.56 51.378 178.656 ;
      RECT 0.048 179.328 51.378 179.424 ;
      RECT 0.048 180.096 51.378 180.192 ;
      RECT 0.048 180.864 51.378 180.96 ;
      RECT 0.048 181.632 51.378 181.728 ;
      RECT 0.048 182.4 51.378 182.496 ;
      RECT 0.048 183.168 51.378 183.264 ;
      RECT 0.048 183.936 51.378 184.032 ;
      RECT 0.048 184.704 51.378 184.8 ;
      RECT 0.048 185.472 51.378 185.568 ;
      RECT 0.048 186.24 51.378 186.336 ;
      RECT 0.048 187.008 51.378 187.104 ;
      RECT 0.048 187.776 51.378 187.872 ;
      RECT 0.048 188.544 51.378 188.64 ;
      RECT 0.048 189.312 51.378 189.408 ;
      RECT 0.048 190.08 51.378 190.176 ;
      RECT 0.048 190.848 51.378 190.944 ;
      RECT 0.048 191.616 51.378 191.712 ;
      RECT 0.048 192.384 51.378 192.48 ;
      RECT 0.048 193.152 51.378 193.248 ;
      RECT 0.048 193.92 51.378 194.016 ;
      RECT 0.048 194.688 51.378 194.784 ;
      RECT 0.048 195.456 51.378 195.552 ;
      RECT 0.048 196.224 51.378 196.32 ;
      RECT 0.048 196.992 51.378 197.088 ;
      RECT 0.048 197.76 51.378 197.856 ;
      RECT 0.048 198.528 51.378 198.624 ;
      RECT 0.048 199.296 51.378 199.392 ;
      RECT 0.048 200.064 51.378 200.16 ;
      RECT 0.048 200.832 51.378 200.928 ;
      RECT 0.048 201.6 51.378 201.696 ;
      RECT 0.048 202.368 51.378 202.464 ;
      RECT 0.048 203.136 51.378 203.232 ;
      RECT 0.048 203.904 51.378 204 ;
      RECT 0.048 204.672 51.378 204.768 ;
      RECT 0.048 205.44 51.378 205.536 ;
      RECT 0.048 206.208 51.378 206.304 ;
      RECT 0.048 206.976 51.378 207.072 ;
      RECT 0.048 207.744 51.378 207.84 ;
      RECT 0.048 208.512 51.378 208.608 ;
      RECT 0.048 209.28 51.378 209.376 ;
      RECT 0.048 210.048 51.378 210.144 ;
      RECT 0.048 210.816 51.378 210.912 ;
      RECT 0.048 211.584 51.378 211.68 ;
      RECT 0.048 212.352 51.378 212.448 ;
      RECT 0.048 213.12 51.378 213.216 ;
      RECT 0.048 213.888 51.378 213.984 ;
      RECT 0.048 214.656 51.378 214.752 ;
      RECT 0.048 215.424 51.378 215.52 ;
      RECT 0.048 216.192 51.378 216.288 ;
      RECT 0.048 216.96 51.378 217.056 ;
      RECT 0.048 217.728 51.378 217.824 ;
      RECT 0.048 218.496 51.378 218.592 ;
      RECT 0.048 219.264 51.378 219.36 ;
      RECT 0.048 220.032 51.378 220.128 ;
      RECT 0.048 220.8 51.378 220.896 ;
      RECT 0.048 221.568 51.378 221.664 ;
      RECT 0.048 222.336 51.378 222.432 ;
      RECT 0.048 223.104 51.378 223.2 ;
      RECT 0.048 223.872 51.378 223.968 ;
      RECT 0.048 224.64 51.378 224.736 ;
      RECT 0.048 225.408 51.378 225.504 ;
      RECT 0.048 226.176 51.378 226.272 ;
      RECT 0.048 226.944 51.378 227.04 ;
      RECT 0.048 227.712 51.378 227.808 ;
      RECT 0.048 228.48 51.378 228.576 ;
      RECT 0.048 229.248 51.378 229.344 ;
      RECT 0.048 230.016 51.378 230.112 ;
      RECT 0.048 230.784 51.378 230.88 ;
      RECT 0.048 231.552 51.378 231.648 ;
      RECT 0.048 232.32 51.378 232.416 ;
      RECT 0.048 233.088 51.378 233.184 ;
      RECT 0.048 233.856 51.378 233.952 ;
      RECT 0.048 234.624 51.378 234.72 ;
      RECT 0.048 235.392 51.378 235.488 ;
      RECT 0.048 236.16 51.378 236.256 ;
      RECT 0.048 236.928 51.378 237.024 ;
      RECT 0.048 237.696 51.378 237.792 ;
      RECT 0.048 238.464 51.378 238.56 ;
      RECT 0.048 239.232 51.378 239.328 ;
      RECT 0.048 240 51.378 240.096 ;
      RECT 0.048 240.768 51.378 240.864 ;
      RECT 0.048 241.536 51.378 241.632 ;
      RECT 0.048 242.304 51.378 242.4 ;
      RECT 0.048 243.072 51.378 243.168 ;
      RECT 0.048 243.84 51.378 243.936 ;
      RECT 0.048 244.608 51.378 244.704 ;
      RECT 0.048 245.376 51.378 245.472 ;
      RECT 0.048 246.144 51.378 246.24 ;
      RECT 0.048 246.912 51.378 247.008 ;
      RECT 0.048 247.68 51.378 247.776 ;
      RECT 0.048 248.448 51.378 248.544 ;
      RECT 0.048 249.216 51.378 249.312 ;
      RECT 0.048 249.984 51.378 250.08 ;
      RECT 0.048 250.752 51.378 250.848 ;
      RECT 0.048 251.52 51.378 251.616 ;
      RECT 0.048 252.288 51.378 252.384 ;
      RECT 0.048 253.056 51.378 253.152 ;
      RECT 0.048 253.824 51.378 253.92 ;
      RECT 0.048 254.592 51.378 254.688 ;
      RECT 0.048 255.36 51.378 255.456 ;
      RECT 0.048 256.128 51.378 256.224 ;
      RECT 0.048 256.896 51.378 256.992 ;
      RECT 0.048 257.664 51.378 257.76 ;
      RECT 0.048 258.432 51.378 258.528 ;
      RECT 0.048 259.2 51.378 259.296 ;
      RECT 0.048 259.968 51.378 260.064 ;
      RECT 0.048 260.736 51.378 260.832 ;
      RECT 0.048 261.504 51.378 261.6 ;
      RECT 0.048 262.272 51.378 262.368 ;
      RECT 0.048 263.04 51.378 263.136 ;
      RECT 0.048 263.808 51.378 263.904 ;
      RECT 0.048 264.576 51.378 264.672 ;
    END
  END VDD
  OBS
    LAYER M1 ;
    RECT 0 0 51.426 265.162 ;
    LAYER M2 ;
    RECT 0 0 51.426 265.162 ;
    LAYER M3 ;
    RECT 0 0 51.426 265.162 ;
  END
END ht_asap7_leon3vtabus_tensorFile_0_2_ext

END LIBRARY
